# Generated by FakeRAM 2.0
VERSION 5.7 ;
BUSBITCHARS "[]" ;
PROPERTYDEFINITIONS
  MACRO width INTEGER ;
  MACRO depth INTEGER ;
  MACRO banks INTEGER ;
END PROPERTYDEFINITIONS
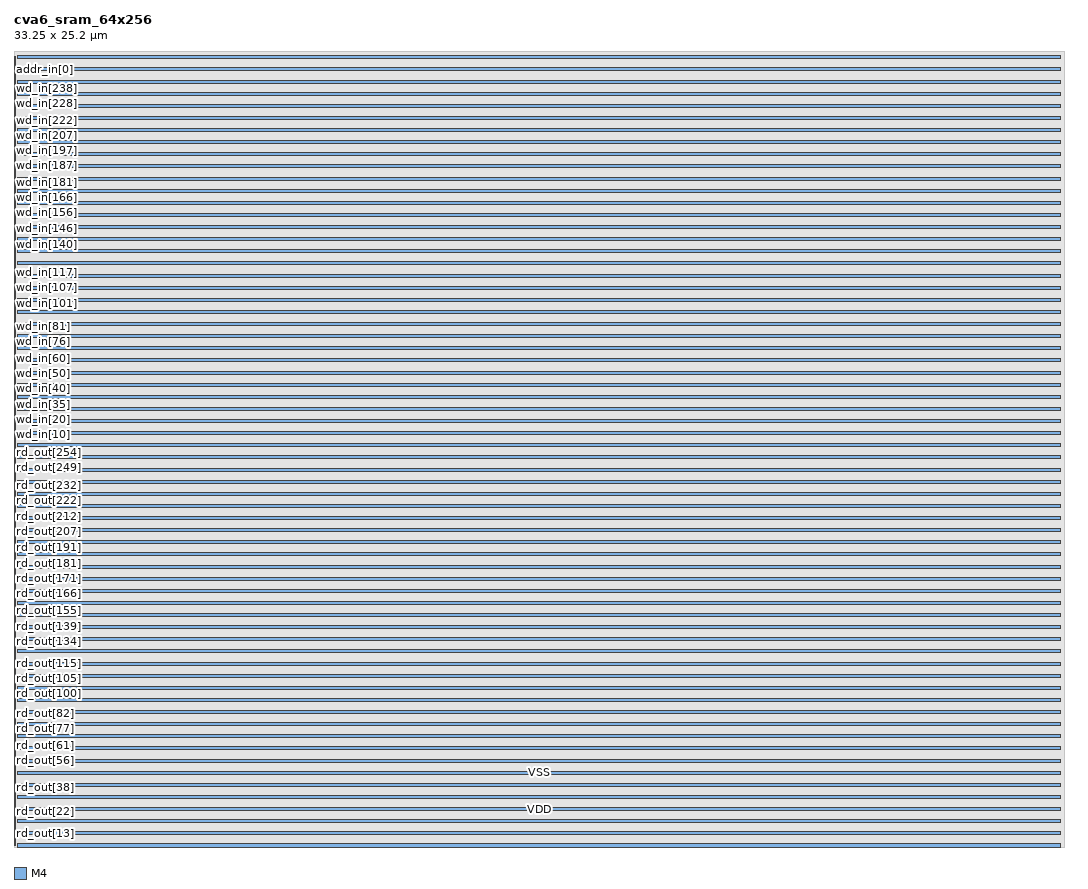
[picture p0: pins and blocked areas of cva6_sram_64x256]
MACRO cva6_sram_64x256
  PROPERTY width 256 ;
  PROPERTY depth 64 ;
  PROPERTY banks 1 ;
  FOREIGN cva6_sram_64x256 0 0 ;
  SYMMETRY X Y R90 ;
  SIZE 33.2500 BY 25.2000 ;
  CLASS BLOCK ;
  PIN rd_out[0]
    DIRECTION OUTPUT ;
    USE SIGNAL ;
    PORT
      LAYER M4 ;
      RECT 0.00000 0.04800 0.03600 0.07200 ;
    END
  END rd_out[0]
  PIN rd_out[1]
    DIRECTION OUTPUT ;
    USE SIGNAL ;
    PORT
      LAYER M4 ;
      RECT 0.00000 0.09600 0.03600 0.12000 ;
    END
  END rd_out[1]
  PIN rd_out[2]
    DIRECTION OUTPUT ;
    USE SIGNAL ;
    PORT
      LAYER M4 ;
      RECT 0.00000 0.14400 0.03600 0.16800 ;
    END
  END rd_out[2]
  PIN rd_out[3]
    DIRECTION OUTPUT ;
    USE SIGNAL ;
    PORT
      LAYER M4 ;
      RECT 0.00000 0.19200 0.03600 0.21600 ;
    END
  END rd_out[3]
  PIN rd_out[4]
    DIRECTION OUTPUT ;
    USE SIGNAL ;
    PORT
      LAYER M4 ;
      RECT 0.00000 0.24000 0.03600 0.26400 ;
    END
  END rd_out[4]
  PIN rd_out[5]
    DIRECTION OUTPUT ;
    USE SIGNAL ;
    PORT
      LAYER M4 ;
      RECT 0.00000 0.28800 0.03600 0.31200 ;
    END
  END rd_out[5]
  PIN rd_out[6]
    DIRECTION OUTPUT ;
    USE SIGNAL ;
    PORT
      LAYER M4 ;
      RECT 0.00000 0.33600 0.03600 0.36000 ;
    END
  END rd_out[6]
  PIN rd_out[7]
    DIRECTION OUTPUT ;
    USE SIGNAL ;
    PORT
      LAYER M4 ;
      RECT 0.00000 0.38400 0.03600 0.40800 ;
    END
  END rd_out[7]
  PIN rd_out[8]
    DIRECTION OUTPUT ;
    USE SIGNAL ;
    PORT
      LAYER M4 ;
      RECT 0.00000 0.43200 0.03600 0.45600 ;
    END
  END rd_out[8]
  PIN rd_out[9]
    DIRECTION OUTPUT ;
    USE SIGNAL ;
    PORT
      LAYER M4 ;
      RECT 0.00000 0.48000 0.03600 0.50400 ;
    END
  END rd_out[9]
  PIN rd_out[10]
    DIRECTION OUTPUT ;
    USE SIGNAL ;
    PORT
      LAYER M4 ;
      RECT 0.00000 0.52800 0.03600 0.55200 ;
    END
  END rd_out[10]
  PIN rd_out[11]
    DIRECTION OUTPUT ;
    USE SIGNAL ;
    PORT
      LAYER M4 ;
      RECT 0.00000 0.57600 0.03600 0.60000 ;
    END
  END rd_out[11]
  PIN rd_out[12]
    DIRECTION OUTPUT ;
    USE SIGNAL ;
    PORT
      LAYER M4 ;
      RECT 0.00000 0.62400 0.03600 0.64800 ;
    END
  END rd_out[12]
  PIN rd_out[13]
    DIRECTION OUTPUT ;
    USE SIGNAL ;
    PORT
      LAYER M4 ;
      RECT 0.00000 0.67200 0.03600 0.69600 ;
    END
  END rd_out[13]
  PIN rd_out[14]
    DIRECTION OUTPUT ;
    USE SIGNAL ;
    PORT
      LAYER M4 ;
      RECT 0.00000 0.72000 0.03600 0.74400 ;
    END
  END rd_out[14]
  PIN rd_out[15]
    DIRECTION OUTPUT ;
    USE SIGNAL ;
    PORT
      LAYER M4 ;
      RECT 0.00000 0.76800 0.03600 0.79200 ;
    END
  END rd_out[15]
  PIN rd_out[16]
    DIRECTION OUTPUT ;
    USE SIGNAL ;
    PORT
      LAYER M4 ;
      RECT 0.00000 0.81600 0.03600 0.84000 ;
    END
  END rd_out[16]
  PIN rd_out[17]
    DIRECTION OUTPUT ;
    USE SIGNAL ;
    PORT
      LAYER M4 ;
      RECT 0.00000 0.86400 0.03600 0.88800 ;
    END
  END rd_out[17]
  PIN rd_out[18]
    DIRECTION OUTPUT ;
    USE SIGNAL ;
    PORT
      LAYER M4 ;
      RECT 0.00000 0.91200 0.03600 0.93600 ;
    END
  END rd_out[18]
  PIN rd_out[19]
    DIRECTION OUTPUT ;
    USE SIGNAL ;
    PORT
      LAYER M4 ;
      RECT 0.00000 0.96000 0.03600 0.98400 ;
    END
  END rd_out[19]
  PIN rd_out[20]
    DIRECTION OUTPUT ;
    USE SIGNAL ;
    PORT
      LAYER M4 ;
      RECT 0.00000 1.00800 0.03600 1.03200 ;
    END
  END rd_out[20]
  PIN rd_out[21]
    DIRECTION OUTPUT ;
    USE SIGNAL ;
    PORT
      LAYER M4 ;
      RECT 0.00000 1.05600 0.03600 1.08000 ;
    END
  END rd_out[21]
  PIN rd_out[22]
    DIRECTION OUTPUT ;
    USE SIGNAL ;
    PORT
      LAYER M4 ;
      RECT 0.00000 1.10400 0.03600 1.12800 ;
    END
  END rd_out[22]
  PIN rd_out[23]
    DIRECTION OUTPUT ;
    USE SIGNAL ;
    PORT
      LAYER M4 ;
      RECT 0.00000 1.15200 0.03600 1.17600 ;
    END
  END rd_out[23]
  PIN rd_out[24]
    DIRECTION OUTPUT ;
    USE SIGNAL ;
    PORT
      LAYER M4 ;
      RECT 0.00000 1.20000 0.03600 1.22400 ;
    END
  END rd_out[24]
  PIN rd_out[25]
    DIRECTION OUTPUT ;
    USE SIGNAL ;
    PORT
      LAYER M4 ;
      RECT 0.00000 1.24800 0.03600 1.27200 ;
    END
  END rd_out[25]
  PIN rd_out[26]
    DIRECTION OUTPUT ;
    USE SIGNAL ;
    PORT
      LAYER M4 ;
      RECT 0.00000 1.29600 0.03600 1.32000 ;
    END
  END rd_out[26]
  PIN rd_out[27]
    DIRECTION OUTPUT ;
    USE SIGNAL ;
    PORT
      LAYER M4 ;
      RECT 0.00000 1.34400 0.03600 1.36800 ;
    END
  END rd_out[27]
  PIN rd_out[28]
    DIRECTION OUTPUT ;
    USE SIGNAL ;
    PORT
      LAYER M4 ;
      RECT 0.00000 1.39200 0.03600 1.41600 ;
    END
  END rd_out[28]
  PIN rd_out[29]
    DIRECTION OUTPUT ;
    USE SIGNAL ;
    PORT
      LAYER M4 ;
      RECT 0.00000 1.44000 0.03600 1.46400 ;
    END
  END rd_out[29]
  PIN rd_out[30]
    DIRECTION OUTPUT ;
    USE SIGNAL ;
    PORT
      LAYER M4 ;
      RECT 0.00000 1.48800 0.03600 1.51200 ;
    END
  END rd_out[30]
  PIN rd_out[31]
    DIRECTION OUTPUT ;
    USE SIGNAL ;
    PORT
      LAYER M4 ;
      RECT 0.00000 1.53600 0.03600 1.56000 ;
    END
  END rd_out[31]
  PIN rd_out[32]
    DIRECTION OUTPUT ;
    USE SIGNAL ;
    PORT
      LAYER M4 ;
      RECT 0.00000 1.58400 0.03600 1.60800 ;
    END
  END rd_out[32]
  PIN rd_out[33]
    DIRECTION OUTPUT ;
    USE SIGNAL ;
    PORT
      LAYER M4 ;
      RECT 0.00000 1.63200 0.03600 1.65600 ;
    END
  END rd_out[33]
  PIN rd_out[34]
    DIRECTION OUTPUT ;
    USE SIGNAL ;
    PORT
      LAYER M4 ;
      RECT 0.00000 1.68000 0.03600 1.70400 ;
    END
  END rd_out[34]
  PIN rd_out[35]
    DIRECTION OUTPUT ;
    USE SIGNAL ;
    PORT
      LAYER M4 ;
      RECT 0.00000 1.72800 0.03600 1.75200 ;
    END
  END rd_out[35]
  PIN rd_out[36]
    DIRECTION OUTPUT ;
    USE SIGNAL ;
    PORT
      LAYER M4 ;
      RECT 0.00000 1.77600 0.03600 1.80000 ;
    END
  END rd_out[36]
  PIN rd_out[37]
    DIRECTION OUTPUT ;
    USE SIGNAL ;
    PORT
      LAYER M4 ;
      RECT 0.00000 1.82400 0.03600 1.84800 ;
    END
  END rd_out[37]
  PIN rd_out[38]
    DIRECTION OUTPUT ;
    USE SIGNAL ;
    PORT
      LAYER M4 ;
      RECT 0.00000 1.87200 0.03600 1.89600 ;
    END
  END rd_out[38]
  PIN rd_out[39]
    DIRECTION OUTPUT ;
    USE SIGNAL ;
    PORT
      LAYER M4 ;
      RECT 0.00000 1.92000 0.03600 1.94400 ;
    END
  END rd_out[39]
  PIN rd_out[40]
    DIRECTION OUTPUT ;
    USE SIGNAL ;
    PORT
      LAYER M4 ;
      RECT 0.00000 1.96800 0.03600 1.99200 ;
    END
  END rd_out[40]
  PIN rd_out[41]
    DIRECTION OUTPUT ;
    USE SIGNAL ;
    PORT
      LAYER M4 ;
      RECT 0.00000 2.01600 0.03600 2.04000 ;
    END
  END rd_out[41]
  PIN rd_out[42]
    DIRECTION OUTPUT ;
    USE SIGNAL ;
    PORT
      LAYER M4 ;
      RECT 0.00000 2.06400 0.03600 2.08800 ;
    END
  END rd_out[42]
  PIN rd_out[43]
    DIRECTION OUTPUT ;
    USE SIGNAL ;
    PORT
      LAYER M4 ;
      RECT 0.00000 2.11200 0.03600 2.13600 ;
    END
  END rd_out[43]
  PIN rd_out[44]
    DIRECTION OUTPUT ;
    USE SIGNAL ;
    PORT
      LAYER M4 ;
      RECT 0.00000 2.16000 0.03600 2.18400 ;
    END
  END rd_out[44]
  PIN rd_out[45]
    DIRECTION OUTPUT ;
    USE SIGNAL ;
    PORT
      LAYER M4 ;
      RECT 0.00000 2.20800 0.03600 2.23200 ;
    END
  END rd_out[45]
  PIN rd_out[46]
    DIRECTION OUTPUT ;
    USE SIGNAL ;
    PORT
      LAYER M4 ;
      RECT 0.00000 2.25600 0.03600 2.28000 ;
    END
  END rd_out[46]
  PIN rd_out[47]
    DIRECTION OUTPUT ;
    USE SIGNAL ;
    PORT
      LAYER M4 ;
      RECT 0.00000 2.30400 0.03600 2.32800 ;
    END
  END rd_out[47]
  PIN rd_out[48]
    DIRECTION OUTPUT ;
    USE SIGNAL ;
    PORT
      LAYER M4 ;
      RECT 0.00000 2.35200 0.03600 2.37600 ;
    END
  END rd_out[48]
  PIN rd_out[49]
    DIRECTION OUTPUT ;
    USE SIGNAL ;
    PORT
      LAYER M4 ;
      RECT 0.00000 2.40000 0.03600 2.42400 ;
    END
  END rd_out[49]
  PIN rd_out[50]
    DIRECTION OUTPUT ;
    USE SIGNAL ;
    PORT
      LAYER M4 ;
      RECT 0.00000 2.44800 0.03600 2.47200 ;
    END
  END rd_out[50]
  PIN rd_out[51]
    DIRECTION OUTPUT ;
    USE SIGNAL ;
    PORT
      LAYER M4 ;
      RECT 0.00000 2.49600 0.03600 2.52000 ;
    END
  END rd_out[51]
  PIN rd_out[52]
    DIRECTION OUTPUT ;
    USE SIGNAL ;
    PORT
      LAYER M4 ;
      RECT 0.00000 2.54400 0.03600 2.56800 ;
    END
  END rd_out[52]
  PIN rd_out[53]
    DIRECTION OUTPUT ;
    USE SIGNAL ;
    PORT
      LAYER M4 ;
      RECT 0.00000 2.59200 0.03600 2.61600 ;
    END
  END rd_out[53]
  PIN rd_out[54]
    DIRECTION OUTPUT ;
    USE SIGNAL ;
    PORT
      LAYER M4 ;
      RECT 0.00000 2.64000 0.03600 2.66400 ;
    END
  END rd_out[54]
  PIN rd_out[55]
    DIRECTION OUTPUT ;
    USE SIGNAL ;
    PORT
      LAYER M4 ;
      RECT 0.00000 2.68800 0.03600 2.71200 ;
    END
  END rd_out[55]
  PIN rd_out[56]
    DIRECTION OUTPUT ;
    USE SIGNAL ;
    PORT
      LAYER M4 ;
      RECT 0.00000 2.73600 0.03600 2.76000 ;
    END
  END rd_out[56]
  PIN rd_out[57]
    DIRECTION OUTPUT ;
    USE SIGNAL ;
    PORT
      LAYER M4 ;
      RECT 0.00000 2.78400 0.03600 2.80800 ;
    END
  END rd_out[57]
  PIN rd_out[58]
    DIRECTION OUTPUT ;
    USE SIGNAL ;
    PORT
      LAYER M4 ;
      RECT 0.00000 2.83200 0.03600 2.85600 ;
    END
  END rd_out[58]
  PIN rd_out[59]
    DIRECTION OUTPUT ;
    USE SIGNAL ;
    PORT
      LAYER M4 ;
      RECT 0.00000 2.88000 0.03600 2.90400 ;
    END
  END rd_out[59]
  PIN rd_out[60]
    DIRECTION OUTPUT ;
    USE SIGNAL ;
    PORT
      LAYER M4 ;
      RECT 0.00000 2.92800 0.03600 2.95200 ;
    END
  END rd_out[60]
  PIN rd_out[61]
    DIRECTION OUTPUT ;
    USE SIGNAL ;
    PORT
      LAYER M4 ;
      RECT 0.00000 2.97600 0.03600 3.00000 ;
    END
  END rd_out[61]
  PIN rd_out[62]
    DIRECTION OUTPUT ;
    USE SIGNAL ;
    PORT
      LAYER M4 ;
      RECT 0.00000 3.02400 0.03600 3.04800 ;
    END
  END rd_out[62]
  PIN rd_out[63]
    DIRECTION OUTPUT ;
    USE SIGNAL ;
    PORT
      LAYER M4 ;
      RECT 0.00000 3.07200 0.03600 3.09600 ;
    END
  END rd_out[63]
  PIN rd_out[64]
    DIRECTION OUTPUT ;
    USE SIGNAL ;
    PORT
      LAYER M4 ;
      RECT 0.00000 3.12000 0.03600 3.14400 ;
    END
  END rd_out[64]
  PIN rd_out[65]
    DIRECTION OUTPUT ;
    USE SIGNAL ;
    PORT
      LAYER M4 ;
      RECT 0.00000 3.16800 0.03600 3.19200 ;
    END
  END rd_out[65]
  PIN rd_out[66]
    DIRECTION OUTPUT ;
    USE SIGNAL ;
    PORT
      LAYER M4 ;
      RECT 0.00000 3.21600 0.03600 3.24000 ;
    END
  END rd_out[66]
  PIN rd_out[67]
    DIRECTION OUTPUT ;
    USE SIGNAL ;
    PORT
      LAYER M4 ;
      RECT 0.00000 3.26400 0.03600 3.28800 ;
    END
  END rd_out[67]
  PIN rd_out[68]
    DIRECTION OUTPUT ;
    USE SIGNAL ;
    PORT
      LAYER M4 ;
      RECT 0.00000 3.31200 0.03600 3.33600 ;
    END
  END rd_out[68]
  PIN rd_out[69]
    DIRECTION OUTPUT ;
    USE SIGNAL ;
    PORT
      LAYER M4 ;
      RECT 0.00000 3.36000 0.03600 3.38400 ;
    END
  END rd_out[69]
  PIN rd_out[70]
    DIRECTION OUTPUT ;
    USE SIGNAL ;
    PORT
      LAYER M4 ;
      RECT 0.00000 3.40800 0.03600 3.43200 ;
    END
  END rd_out[70]
  PIN rd_out[71]
    DIRECTION OUTPUT ;
    USE SIGNAL ;
    PORT
      LAYER M4 ;
      RECT 0.00000 3.45600 0.03600 3.48000 ;
    END
  END rd_out[71]
  PIN rd_out[72]
    DIRECTION OUTPUT ;
    USE SIGNAL ;
    PORT
      LAYER M4 ;
      RECT 0.00000 3.50400 0.03600 3.52800 ;
    END
  END rd_out[72]
  PIN rd_out[73]
    DIRECTION OUTPUT ;
    USE SIGNAL ;
    PORT
      LAYER M4 ;
      RECT 0.00000 3.55200 0.03600 3.57600 ;
    END
  END rd_out[73]
  PIN rd_out[74]
    DIRECTION OUTPUT ;
    USE SIGNAL ;
    PORT
      LAYER M4 ;
      RECT 0.00000 3.60000 0.03600 3.62400 ;
    END
  END rd_out[74]
  PIN rd_out[75]
    DIRECTION OUTPUT ;
    USE SIGNAL ;
    PORT
      LAYER M4 ;
      RECT 0.00000 3.64800 0.03600 3.67200 ;
    END
  END rd_out[75]
  PIN rd_out[76]
    DIRECTION OUTPUT ;
    USE SIGNAL ;
    PORT
      LAYER M4 ;
      RECT 0.00000 3.69600 0.03600 3.72000 ;
    END
  END rd_out[76]
  PIN rd_out[77]
    DIRECTION OUTPUT ;
    USE SIGNAL ;
    PORT
      LAYER M4 ;
      RECT 0.00000 3.74400 0.03600 3.76800 ;
    END
  END rd_out[77]
  PIN rd_out[78]
    DIRECTION OUTPUT ;
    USE SIGNAL ;
    PORT
      LAYER M4 ;
      RECT 0.00000 3.79200 0.03600 3.81600 ;
    END
  END rd_out[78]
  PIN rd_out[79]
    DIRECTION OUTPUT ;
    USE SIGNAL ;
    PORT
      LAYER M4 ;
      RECT 0.00000 3.84000 0.03600 3.86400 ;
    END
  END rd_out[79]
  PIN rd_out[80]
    DIRECTION OUTPUT ;
    USE SIGNAL ;
    PORT
      LAYER M4 ;
      RECT 0.00000 3.88800 0.03600 3.91200 ;
    END
  END rd_out[80]
  PIN rd_out[81]
    DIRECTION OUTPUT ;
    USE SIGNAL ;
    PORT
      LAYER M4 ;
      RECT 0.00000 3.93600 0.03600 3.96000 ;
    END
  END rd_out[81]
  PIN rd_out[82]
    DIRECTION OUTPUT ;
    USE SIGNAL ;
    PORT
      LAYER M4 ;
      RECT 0.00000 3.98400 0.03600 4.00800 ;
    END
  END rd_out[82]
  PIN rd_out[83]
    DIRECTION OUTPUT ;
    USE SIGNAL ;
    PORT
      LAYER M4 ;
      RECT 0.00000 4.03200 0.03600 4.05600 ;
    END
  END rd_out[83]
  PIN rd_out[84]
    DIRECTION OUTPUT ;
    USE SIGNAL ;
    PORT
      LAYER M4 ;
      RECT 0.00000 4.08000 0.03600 4.10400 ;
    END
  END rd_out[84]
  PIN rd_out[85]
    DIRECTION OUTPUT ;
    USE SIGNAL ;
    PORT
      LAYER M4 ;
      RECT 0.00000 4.12800 0.03600 4.15200 ;
    END
  END rd_out[85]
  PIN rd_out[86]
    DIRECTION OUTPUT ;
    USE SIGNAL ;
    PORT
      LAYER M4 ;
      RECT 0.00000 4.17600 0.03600 4.20000 ;
    END
  END rd_out[86]
  PIN rd_out[87]
    DIRECTION OUTPUT ;
    USE SIGNAL ;
    PORT
      LAYER M4 ;
      RECT 0.00000 4.22400 0.03600 4.24800 ;
    END
  END rd_out[87]
  PIN rd_out[88]
    DIRECTION OUTPUT ;
    USE SIGNAL ;
    PORT
      LAYER M4 ;
      RECT 0.00000 4.27200 0.03600 4.29600 ;
    END
  END rd_out[88]
  PIN rd_out[89]
    DIRECTION OUTPUT ;
    USE SIGNAL ;
    PORT
      LAYER M4 ;
      RECT 0.00000 4.32000 0.03600 4.34400 ;
    END
  END rd_out[89]
  PIN rd_out[90]
    DIRECTION OUTPUT ;
    USE SIGNAL ;
    PORT
      LAYER M4 ;
      RECT 0.00000 4.36800 0.03600 4.39200 ;
    END
  END rd_out[90]
  PIN rd_out[91]
    DIRECTION OUTPUT ;
    USE SIGNAL ;
    PORT
      LAYER M4 ;
      RECT 0.00000 4.41600 0.03600 4.44000 ;
    END
  END rd_out[91]
  PIN rd_out[92]
    DIRECTION OUTPUT ;
    USE SIGNAL ;
    PORT
      LAYER M4 ;
      RECT 0.00000 4.46400 0.03600 4.48800 ;
    END
  END rd_out[92]
  PIN rd_out[93]
    DIRECTION OUTPUT ;
    USE SIGNAL ;
    PORT
      LAYER M4 ;
      RECT 0.00000 4.51200 0.03600 4.53600 ;
    END
  END rd_out[93]
  PIN rd_out[94]
    DIRECTION OUTPUT ;
    USE SIGNAL ;
    PORT
      LAYER M4 ;
      RECT 0.00000 4.56000 0.03600 4.58400 ;
    END
  END rd_out[94]
  PIN rd_out[95]
    DIRECTION OUTPUT ;
    USE SIGNAL ;
    PORT
      LAYER M4 ;
      RECT 0.00000 4.60800 0.03600 4.63200 ;
    END
  END rd_out[95]
  PIN rd_out[96]
    DIRECTION OUTPUT ;
    USE SIGNAL ;
    PORT
      LAYER M4 ;
      RECT 0.00000 4.65600 0.03600 4.68000 ;
    END
  END rd_out[96]
  PIN rd_out[97]
    DIRECTION OUTPUT ;
    USE SIGNAL ;
    PORT
      LAYER M4 ;
      RECT 0.00000 4.70400 0.03600 4.72800 ;
    END
  END rd_out[97]
  PIN rd_out[98]
    DIRECTION OUTPUT ;
    USE SIGNAL ;
    PORT
      LAYER M4 ;
      RECT 0.00000 4.75200 0.03600 4.77600 ;
    END
  END rd_out[98]
  PIN rd_out[99]
    DIRECTION OUTPUT ;
    USE SIGNAL ;
    PORT
      LAYER M4 ;
      RECT 0.00000 4.80000 0.03600 4.82400 ;
    END
  END rd_out[99]
  PIN rd_out[100]
    DIRECTION OUTPUT ;
    USE SIGNAL ;
    PORT
      LAYER M4 ;
      RECT 0.00000 4.84800 0.03600 4.87200 ;
    END
  END rd_out[100]
  PIN rd_out[101]
    DIRECTION OUTPUT ;
    USE SIGNAL ;
    PORT
      LAYER M4 ;
      RECT 0.00000 4.89600 0.03600 4.92000 ;
    END
  END rd_out[101]
  PIN rd_out[102]
    DIRECTION OUTPUT ;
    USE SIGNAL ;
    PORT
      LAYER M4 ;
      RECT 0.00000 4.94400 0.03600 4.96800 ;
    END
  END rd_out[102]
  PIN rd_out[103]
    DIRECTION OUTPUT ;
    USE SIGNAL ;
    PORT
      LAYER M4 ;
      RECT 0.00000 4.99200 0.03600 5.01600 ;
    END
  END rd_out[103]
  PIN rd_out[104]
    DIRECTION OUTPUT ;
    USE SIGNAL ;
    PORT
      LAYER M4 ;
      RECT 0.00000 5.04000 0.03600 5.06400 ;
    END
  END rd_out[104]
  PIN rd_out[105]
    DIRECTION OUTPUT ;
    USE SIGNAL ;
    PORT
      LAYER M4 ;
      RECT 0.00000 5.08800 0.03600 5.11200 ;
    END
  END rd_out[105]
  PIN rd_out[106]
    DIRECTION OUTPUT ;
    USE SIGNAL ;
    PORT
      LAYER M4 ;
      RECT 0.00000 5.13600 0.03600 5.16000 ;
    END
  END rd_out[106]
  PIN rd_out[107]
    DIRECTION OUTPUT ;
    USE SIGNAL ;
    PORT
      LAYER M4 ;
      RECT 0.00000 5.18400 0.03600 5.20800 ;
    END
  END rd_out[107]
  PIN rd_out[108]
    DIRECTION OUTPUT ;
    USE SIGNAL ;
    PORT
      LAYER M4 ;
      RECT 0.00000 5.23200 0.03600 5.25600 ;
    END
  END rd_out[108]
  PIN rd_out[109]
    DIRECTION OUTPUT ;
    USE SIGNAL ;
    PORT
      LAYER M4 ;
      RECT 0.00000 5.28000 0.03600 5.30400 ;
    END
  END rd_out[109]
  PIN rd_out[110]
    DIRECTION OUTPUT ;
    USE SIGNAL ;
    PORT
      LAYER M4 ;
      RECT 0.00000 5.32800 0.03600 5.35200 ;
    END
  END rd_out[110]
  PIN rd_out[111]
    DIRECTION OUTPUT ;
    USE SIGNAL ;
    PORT
      LAYER M4 ;
      RECT 0.00000 5.37600 0.03600 5.40000 ;
    END
  END rd_out[111]
  PIN rd_out[112]
    DIRECTION OUTPUT ;
    USE SIGNAL ;
    PORT
      LAYER M4 ;
      RECT 0.00000 5.42400 0.03600 5.44800 ;
    END
  END rd_out[112]
  PIN rd_out[113]
    DIRECTION OUTPUT ;
    USE SIGNAL ;
    PORT
      LAYER M4 ;
      RECT 0.00000 5.47200 0.03600 5.49600 ;
    END
  END rd_out[113]
  PIN rd_out[114]
    DIRECTION OUTPUT ;
    USE SIGNAL ;
    PORT
      LAYER M4 ;
      RECT 0.00000 5.52000 0.03600 5.54400 ;
    END
  END rd_out[114]
  PIN rd_out[115]
    DIRECTION OUTPUT ;
    USE SIGNAL ;
    PORT
      LAYER M4 ;
      RECT 0.00000 5.56800 0.03600 5.59200 ;
    END
  END rd_out[115]
  PIN rd_out[116]
    DIRECTION OUTPUT ;
    USE SIGNAL ;
    PORT
      LAYER M4 ;
      RECT 0.00000 5.61600 0.03600 5.64000 ;
    END
  END rd_out[116]
  PIN rd_out[117]
    DIRECTION OUTPUT ;
    USE SIGNAL ;
    PORT
      LAYER M4 ;
      RECT 0.00000 5.66400 0.03600 5.68800 ;
    END
  END rd_out[117]
  PIN rd_out[118]
    DIRECTION OUTPUT ;
    USE SIGNAL ;
    PORT
      LAYER M4 ;
      RECT 0.00000 5.71200 0.03600 5.73600 ;
    END
  END rd_out[118]
  PIN rd_out[119]
    DIRECTION OUTPUT ;
    USE SIGNAL ;
    PORT
      LAYER M4 ;
      RECT 0.00000 5.76000 0.03600 5.78400 ;
    END
  END rd_out[119]
  PIN rd_out[120]
    DIRECTION OUTPUT ;
    USE SIGNAL ;
    PORT
      LAYER M4 ;
      RECT 0.00000 5.80800 0.03600 5.83200 ;
    END
  END rd_out[120]
  PIN rd_out[121]
    DIRECTION OUTPUT ;
    USE SIGNAL ;
    PORT
      LAYER M4 ;
      RECT 0.00000 5.85600 0.03600 5.88000 ;
    END
  END rd_out[121]
  PIN rd_out[122]
    DIRECTION OUTPUT ;
    USE SIGNAL ;
    PORT
      LAYER M4 ;
      RECT 0.00000 5.90400 0.03600 5.92800 ;
    END
  END rd_out[122]
  PIN rd_out[123]
    DIRECTION OUTPUT ;
    USE SIGNAL ;
    PORT
      LAYER M4 ;
      RECT 0.00000 5.95200 0.03600 5.97600 ;
    END
  END rd_out[123]
  PIN rd_out[124]
    DIRECTION OUTPUT ;
    USE SIGNAL ;
    PORT
      LAYER M4 ;
      RECT 0.00000 6.00000 0.03600 6.02400 ;
    END
  END rd_out[124]
  PIN rd_out[125]
    DIRECTION OUTPUT ;
    USE SIGNAL ;
    PORT
      LAYER M4 ;
      RECT 0.00000 6.04800 0.03600 6.07200 ;
    END
  END rd_out[125]
  PIN rd_out[126]
    DIRECTION OUTPUT ;
    USE SIGNAL ;
    PORT
      LAYER M4 ;
      RECT 0.00000 6.09600 0.03600 6.12000 ;
    END
  END rd_out[126]
  PIN rd_out[127]
    DIRECTION OUTPUT ;
    USE SIGNAL ;
    PORT
      LAYER M4 ;
      RECT 0.00000 6.14400 0.03600 6.16800 ;
    END
  END rd_out[127]
  PIN rd_out[128]
    DIRECTION OUTPUT ;
    USE SIGNAL ;
    PORT
      LAYER M4 ;
      RECT 0.00000 6.19200 0.03600 6.21600 ;
    END
  END rd_out[128]
  PIN rd_out[129]
    DIRECTION OUTPUT ;
    USE SIGNAL ;
    PORT
      LAYER M4 ;
      RECT 0.00000 6.24000 0.03600 6.26400 ;
    END
  END rd_out[129]
  PIN rd_out[130]
    DIRECTION OUTPUT ;
    USE SIGNAL ;
    PORT
      LAYER M4 ;
      RECT 0.00000 6.28800 0.03600 6.31200 ;
    END
  END rd_out[130]
  PIN rd_out[131]
    DIRECTION OUTPUT ;
    USE SIGNAL ;
    PORT
      LAYER M4 ;
      RECT 0.00000 6.33600 0.03600 6.36000 ;
    END
  END rd_out[131]
  PIN rd_out[132]
    DIRECTION OUTPUT ;
    USE SIGNAL ;
    PORT
      LAYER M4 ;
      RECT 0.00000 6.38400 0.03600 6.40800 ;
    END
  END rd_out[132]
  PIN rd_out[133]
    DIRECTION OUTPUT ;
    USE SIGNAL ;
    PORT
      LAYER M4 ;
      RECT 0.00000 6.43200 0.03600 6.45600 ;
    END
  END rd_out[133]
  PIN rd_out[134]
    DIRECTION OUTPUT ;
    USE SIGNAL ;
    PORT
      LAYER M4 ;
      RECT 0.00000 6.48000 0.03600 6.50400 ;
    END
  END rd_out[134]
  PIN rd_out[135]
    DIRECTION OUTPUT ;
    USE SIGNAL ;
    PORT
      LAYER M4 ;
      RECT 0.00000 6.52800 0.03600 6.55200 ;
    END
  END rd_out[135]
  PIN rd_out[136]
    DIRECTION OUTPUT ;
    USE SIGNAL ;
    PORT
      LAYER M4 ;
      RECT 0.00000 6.57600 0.03600 6.60000 ;
    END
  END rd_out[136]
  PIN rd_out[137]
    DIRECTION OUTPUT ;
    USE SIGNAL ;
    PORT
      LAYER M4 ;
      RECT 0.00000 6.62400 0.03600 6.64800 ;
    END
  END rd_out[137]
  PIN rd_out[138]
    DIRECTION OUTPUT ;
    USE SIGNAL ;
    PORT
      LAYER M4 ;
      RECT 0.00000 6.67200 0.03600 6.69600 ;
    END
  END rd_out[138]
  PIN rd_out[139]
    DIRECTION OUTPUT ;
    USE SIGNAL ;
    PORT
      LAYER M4 ;
      RECT 0.00000 6.72000 0.03600 6.74400 ;
    END
  END rd_out[139]
  PIN rd_out[140]
    DIRECTION OUTPUT ;
    USE SIGNAL ;
    PORT
      LAYER M4 ;
      RECT 0.00000 6.76800 0.03600 6.79200 ;
    END
  END rd_out[140]
  PIN rd_out[141]
    DIRECTION OUTPUT ;
    USE SIGNAL ;
    PORT
      LAYER M4 ;
      RECT 0.00000 6.81600 0.03600 6.84000 ;
    END
  END rd_out[141]
  PIN rd_out[142]
    DIRECTION OUTPUT ;
    USE SIGNAL ;
    PORT
      LAYER M4 ;
      RECT 0.00000 6.86400 0.03600 6.88800 ;
    END
  END rd_out[142]
  PIN rd_out[143]
    DIRECTION OUTPUT ;
    USE SIGNAL ;
    PORT
      LAYER M4 ;
      RECT 0.00000 6.91200 0.03600 6.93600 ;
    END
  END rd_out[143]
  PIN rd_out[144]
    DIRECTION OUTPUT ;
    USE SIGNAL ;
    PORT
      LAYER M4 ;
      RECT 0.00000 6.96000 0.03600 6.98400 ;
    END
  END rd_out[144]
  PIN rd_out[145]
    DIRECTION OUTPUT ;
    USE SIGNAL ;
    PORT
      LAYER M4 ;
      RECT 0.00000 7.00800 0.03600 7.03200 ;
    END
  END rd_out[145]
  PIN rd_out[146]
    DIRECTION OUTPUT ;
    USE SIGNAL ;
    PORT
      LAYER M4 ;
      RECT 0.00000 7.05600 0.03600 7.08000 ;
    END
  END rd_out[146]
  PIN rd_out[147]
    DIRECTION OUTPUT ;
    USE SIGNAL ;
    PORT
      LAYER M4 ;
      RECT 0.00000 7.10400 0.03600 7.12800 ;
    END
  END rd_out[147]
  PIN rd_out[148]
    DIRECTION OUTPUT ;
    USE SIGNAL ;
    PORT
      LAYER M4 ;
      RECT 0.00000 7.15200 0.03600 7.17600 ;
    END
  END rd_out[148]
  PIN rd_out[149]
    DIRECTION OUTPUT ;
    USE SIGNAL ;
    PORT
      LAYER M4 ;
      RECT 0.00000 7.20000 0.03600 7.22400 ;
    END
  END rd_out[149]
  PIN rd_out[150]
    DIRECTION OUTPUT ;
    USE SIGNAL ;
    PORT
      LAYER M4 ;
      RECT 0.00000 7.24800 0.03600 7.27200 ;
    END
  END rd_out[150]
  PIN rd_out[151]
    DIRECTION OUTPUT ;
    USE SIGNAL ;
    PORT
      LAYER M4 ;
      RECT 0.00000 7.29600 0.03600 7.32000 ;
    END
  END rd_out[151]
  PIN rd_out[152]
    DIRECTION OUTPUT ;
    USE SIGNAL ;
    PORT
      LAYER M4 ;
      RECT 0.00000 7.34400 0.03600 7.36800 ;
    END
  END rd_out[152]
  PIN rd_out[153]
    DIRECTION OUTPUT ;
    USE SIGNAL ;
    PORT
      LAYER M4 ;
      RECT 0.00000 7.39200 0.03600 7.41600 ;
    END
  END rd_out[153]
  PIN rd_out[154]
    DIRECTION OUTPUT ;
    USE SIGNAL ;
    PORT
      LAYER M4 ;
      RECT 0.00000 7.44000 0.03600 7.46400 ;
    END
  END rd_out[154]
  PIN rd_out[155]
    DIRECTION OUTPUT ;
    USE SIGNAL ;
    PORT
      LAYER M4 ;
      RECT 0.00000 7.48800 0.03600 7.51200 ;
    END
  END rd_out[155]
  PIN rd_out[156]
    DIRECTION OUTPUT ;
    USE SIGNAL ;
    PORT
      LAYER M4 ;
      RECT 0.00000 7.53600 0.03600 7.56000 ;
    END
  END rd_out[156]
  PIN rd_out[157]
    DIRECTION OUTPUT ;
    USE SIGNAL ;
    PORT
      LAYER M4 ;
      RECT 0.00000 7.58400 0.03600 7.60800 ;
    END
  END rd_out[157]
  PIN rd_out[158]
    DIRECTION OUTPUT ;
    USE SIGNAL ;
    PORT
      LAYER M4 ;
      RECT 0.00000 7.63200 0.03600 7.65600 ;
    END
  END rd_out[158]
  PIN rd_out[159]
    DIRECTION OUTPUT ;
    USE SIGNAL ;
    PORT
      LAYER M4 ;
      RECT 0.00000 7.68000 0.03600 7.70400 ;
    END
  END rd_out[159]
  PIN rd_out[160]
    DIRECTION OUTPUT ;
    USE SIGNAL ;
    PORT
      LAYER M4 ;
      RECT 0.00000 7.72800 0.03600 7.75200 ;
    END
  END rd_out[160]
  PIN rd_out[161]
    DIRECTION OUTPUT ;
    USE SIGNAL ;
    PORT
      LAYER M4 ;
      RECT 0.00000 7.77600 0.03600 7.80000 ;
    END
  END rd_out[161]
  PIN rd_out[162]
    DIRECTION OUTPUT ;
    USE SIGNAL ;
    PORT
      LAYER M4 ;
      RECT 0.00000 7.82400 0.03600 7.84800 ;
    END
  END rd_out[162]
  PIN rd_out[163]
    DIRECTION OUTPUT ;
    USE SIGNAL ;
    PORT
      LAYER M4 ;
      RECT 0.00000 7.87200 0.03600 7.89600 ;
    END
  END rd_out[163]
  PIN rd_out[164]
    DIRECTION OUTPUT ;
    USE SIGNAL ;
    PORT
      LAYER M4 ;
      RECT 0.00000 7.92000 0.03600 7.94400 ;
    END
  END rd_out[164]
  PIN rd_out[165]
    DIRECTION OUTPUT ;
    USE SIGNAL ;
    PORT
      LAYER M4 ;
      RECT 0.00000 7.96800 0.03600 7.99200 ;
    END
  END rd_out[165]
  PIN rd_out[166]
    DIRECTION OUTPUT ;
    USE SIGNAL ;
    PORT
      LAYER M4 ;
      RECT 0.00000 8.01600 0.03600 8.04000 ;
    END
  END rd_out[166]
  PIN rd_out[167]
    DIRECTION OUTPUT ;
    USE SIGNAL ;
    PORT
      LAYER M4 ;
      RECT 0.00000 8.06400 0.03600 8.08800 ;
    END
  END rd_out[167]
  PIN rd_out[168]
    DIRECTION OUTPUT ;
    USE SIGNAL ;
    PORT
      LAYER M4 ;
      RECT 0.00000 8.11200 0.03600 8.13600 ;
    END
  END rd_out[168]
  PIN rd_out[169]
    DIRECTION OUTPUT ;
    USE SIGNAL ;
    PORT
      LAYER M4 ;
      RECT 0.00000 8.16000 0.03600 8.18400 ;
    END
  END rd_out[169]
  PIN rd_out[170]
    DIRECTION OUTPUT ;
    USE SIGNAL ;
    PORT
      LAYER M4 ;
      RECT 0.00000 8.20800 0.03600 8.23200 ;
    END
  END rd_out[170]
  PIN rd_out[171]
    DIRECTION OUTPUT ;
    USE SIGNAL ;
    PORT
      LAYER M4 ;
      RECT 0.00000 8.25600 0.03600 8.28000 ;
    END
  END rd_out[171]
  PIN rd_out[172]
    DIRECTION OUTPUT ;
    USE SIGNAL ;
    PORT
      LAYER M4 ;
      RECT 0.00000 8.30400 0.03600 8.32800 ;
    END
  END rd_out[172]
  PIN rd_out[173]
    DIRECTION OUTPUT ;
    USE SIGNAL ;
    PORT
      LAYER M4 ;
      RECT 0.00000 8.35200 0.03600 8.37600 ;
    END
  END rd_out[173]
  PIN rd_out[174]
    DIRECTION OUTPUT ;
    USE SIGNAL ;
    PORT
      LAYER M4 ;
      RECT 0.00000 8.40000 0.03600 8.42400 ;
    END
  END rd_out[174]
  PIN rd_out[175]
    DIRECTION OUTPUT ;
    USE SIGNAL ;
    PORT
      LAYER M4 ;
      RECT 0.00000 8.44800 0.03600 8.47200 ;
    END
  END rd_out[175]
  PIN rd_out[176]
    DIRECTION OUTPUT ;
    USE SIGNAL ;
    PORT
      LAYER M4 ;
      RECT 0.00000 8.49600 0.03600 8.52000 ;
    END
  END rd_out[176]
  PIN rd_out[177]
    DIRECTION OUTPUT ;
    USE SIGNAL ;
    PORT
      LAYER M4 ;
      RECT 0.00000 8.54400 0.03600 8.56800 ;
    END
  END rd_out[177]
  PIN rd_out[178]
    DIRECTION OUTPUT ;
    USE SIGNAL ;
    PORT
      LAYER M4 ;
      RECT 0.00000 8.59200 0.03600 8.61600 ;
    END
  END rd_out[178]
  PIN rd_out[179]
    DIRECTION OUTPUT ;
    USE SIGNAL ;
    PORT
      LAYER M4 ;
      RECT 0.00000 8.64000 0.03600 8.66400 ;
    END
  END rd_out[179]
  PIN rd_out[180]
    DIRECTION OUTPUT ;
    USE SIGNAL ;
    PORT
      LAYER M4 ;
      RECT 0.00000 8.68800 0.03600 8.71200 ;
    END
  END rd_out[180]
  PIN rd_out[181]
    DIRECTION OUTPUT ;
    USE SIGNAL ;
    PORT
      LAYER M4 ;
      RECT 0.00000 8.73600 0.03600 8.76000 ;
    END
  END rd_out[181]
  PIN rd_out[182]
    DIRECTION OUTPUT ;
    USE SIGNAL ;
    PORT
      LAYER M4 ;
      RECT 0.00000 8.78400 0.03600 8.80800 ;
    END
  END rd_out[182]
  PIN rd_out[183]
    DIRECTION OUTPUT ;
    USE SIGNAL ;
    PORT
      LAYER M4 ;
      RECT 0.00000 8.83200 0.03600 8.85600 ;
    END
  END rd_out[183]
  PIN rd_out[184]
    DIRECTION OUTPUT ;
    USE SIGNAL ;
    PORT
      LAYER M4 ;
      RECT 0.00000 8.88000 0.03600 8.90400 ;
    END
  END rd_out[184]
  PIN rd_out[185]
    DIRECTION OUTPUT ;
    USE SIGNAL ;
    PORT
      LAYER M4 ;
      RECT 0.00000 8.92800 0.03600 8.95200 ;
    END
  END rd_out[185]
  PIN rd_out[186]
    DIRECTION OUTPUT ;
    USE SIGNAL ;
    PORT
      LAYER M4 ;
      RECT 0.00000 8.97600 0.03600 9.00000 ;
    END
  END rd_out[186]
  PIN rd_out[187]
    DIRECTION OUTPUT ;
    USE SIGNAL ;
    PORT
      LAYER M4 ;
      RECT 0.00000 9.02400 0.03600 9.04800 ;
    END
  END rd_out[187]
  PIN rd_out[188]
    DIRECTION OUTPUT ;
    USE SIGNAL ;
    PORT
      LAYER M4 ;
      RECT 0.00000 9.07200 0.03600 9.09600 ;
    END
  END rd_out[188]
  PIN rd_out[189]
    DIRECTION OUTPUT ;
    USE SIGNAL ;
    PORT
      LAYER M4 ;
      RECT 0.00000 9.12000 0.03600 9.14400 ;
    END
  END rd_out[189]
  PIN rd_out[190]
    DIRECTION OUTPUT ;
    USE SIGNAL ;
    PORT
      LAYER M4 ;
      RECT 0.00000 9.16800 0.03600 9.19200 ;
    END
  END rd_out[190]
  PIN rd_out[191]
    DIRECTION OUTPUT ;
    USE SIGNAL ;
    PORT
      LAYER M4 ;
      RECT 0.00000 9.21600 0.03600 9.24000 ;
    END
  END rd_out[191]
  PIN rd_out[192]
    DIRECTION OUTPUT ;
    USE SIGNAL ;
    PORT
      LAYER M4 ;
      RECT 0.00000 9.26400 0.03600 9.28800 ;
    END
  END rd_out[192]
  PIN rd_out[193]
    DIRECTION OUTPUT ;
    USE SIGNAL ;
    PORT
      LAYER M4 ;
      RECT 0.00000 9.31200 0.03600 9.33600 ;
    END
  END rd_out[193]
  PIN rd_out[194]
    DIRECTION OUTPUT ;
    USE SIGNAL ;
    PORT
      LAYER M4 ;
      RECT 0.00000 9.36000 0.03600 9.38400 ;
    END
  END rd_out[194]
  PIN rd_out[195]
    DIRECTION OUTPUT ;
    USE SIGNAL ;
    PORT
      LAYER M4 ;
      RECT 0.00000 9.40800 0.03600 9.43200 ;
    END
  END rd_out[195]
  PIN rd_out[196]
    DIRECTION OUTPUT ;
    USE SIGNAL ;
    PORT
      LAYER M4 ;
      RECT 0.00000 9.45600 0.03600 9.48000 ;
    END
  END rd_out[196]
  PIN rd_out[197]
    DIRECTION OUTPUT ;
    USE SIGNAL ;
    PORT
      LAYER M4 ;
      RECT 0.00000 9.50400 0.03600 9.52800 ;
    END
  END rd_out[197]
  PIN rd_out[198]
    DIRECTION OUTPUT ;
    USE SIGNAL ;
    PORT
      LAYER M4 ;
      RECT 0.00000 9.55200 0.03600 9.57600 ;
    END
  END rd_out[198]
  PIN rd_out[199]
    DIRECTION OUTPUT ;
    USE SIGNAL ;
    PORT
      LAYER M4 ;
      RECT 0.00000 9.60000 0.03600 9.62400 ;
    END
  END rd_out[199]
  PIN rd_out[200]
    DIRECTION OUTPUT ;
    USE SIGNAL ;
    PORT
      LAYER M4 ;
      RECT 0.00000 9.64800 0.03600 9.67200 ;
    END
  END rd_out[200]
  PIN rd_out[201]
    DIRECTION OUTPUT ;
    USE SIGNAL ;
    PORT
      LAYER M4 ;
      RECT 0.00000 9.69600 0.03600 9.72000 ;
    END
  END rd_out[201]
  PIN rd_out[202]
    DIRECTION OUTPUT ;
    USE SIGNAL ;
    PORT
      LAYER M4 ;
      RECT 0.00000 9.74400 0.03600 9.76800 ;
    END
  END rd_out[202]
  PIN rd_out[203]
    DIRECTION OUTPUT ;
    USE SIGNAL ;
    PORT
      LAYER M4 ;
      RECT 0.00000 9.79200 0.03600 9.81600 ;
    END
  END rd_out[203]
  PIN rd_out[204]
    DIRECTION OUTPUT ;
    USE SIGNAL ;
    PORT
      LAYER M4 ;
      RECT 0.00000 9.84000 0.03600 9.86400 ;
    END
  END rd_out[204]
  PIN rd_out[205]
    DIRECTION OUTPUT ;
    USE SIGNAL ;
    PORT
      LAYER M4 ;
      RECT 0.00000 9.88800 0.03600 9.91200 ;
    END
  END rd_out[205]
  PIN rd_out[206]
    DIRECTION OUTPUT ;
    USE SIGNAL ;
    PORT
      LAYER M4 ;
      RECT 0.00000 9.93600 0.03600 9.96000 ;
    END
  END rd_out[206]
  PIN rd_out[207]
    DIRECTION OUTPUT ;
    USE SIGNAL ;
    PORT
      LAYER M4 ;
      RECT 0.00000 9.98400 0.03600 10.00800 ;
    END
  END rd_out[207]
  PIN rd_out[208]
    DIRECTION OUTPUT ;
    USE SIGNAL ;
    PORT
      LAYER M4 ;
      RECT 0.00000 10.03200 0.03600 10.05600 ;
    END
  END rd_out[208]
  PIN rd_out[209]
    DIRECTION OUTPUT ;
    USE SIGNAL ;
    PORT
      LAYER M4 ;
      RECT 0.00000 10.08000 0.03600 10.10400 ;
    END
  END rd_out[209]
  PIN rd_out[210]
    DIRECTION OUTPUT ;
    USE SIGNAL ;
    PORT
      LAYER M4 ;
      RECT 0.00000 10.12800 0.03600 10.15200 ;
    END
  END rd_out[210]
  PIN rd_out[211]
    DIRECTION OUTPUT ;
    USE SIGNAL ;
    PORT
      LAYER M4 ;
      RECT 0.00000 10.17600 0.03600 10.20000 ;
    END
  END rd_out[211]
  PIN rd_out[212]
    DIRECTION OUTPUT ;
    USE SIGNAL ;
    PORT
      LAYER M4 ;
      RECT 0.00000 10.22400 0.03600 10.24800 ;
    END
  END rd_out[212]
  PIN rd_out[213]
    DIRECTION OUTPUT ;
    USE SIGNAL ;
    PORT
      LAYER M4 ;
      RECT 0.00000 10.27200 0.03600 10.29600 ;
    END
  END rd_out[213]
  PIN rd_out[214]
    DIRECTION OUTPUT ;
    USE SIGNAL ;
    PORT
      LAYER M4 ;
      RECT 0.00000 10.32000 0.03600 10.34400 ;
    END
  END rd_out[214]
  PIN rd_out[215]
    DIRECTION OUTPUT ;
    USE SIGNAL ;
    PORT
      LAYER M4 ;
      RECT 0.00000 10.36800 0.03600 10.39200 ;
    END
  END rd_out[215]
  PIN rd_out[216]
    DIRECTION OUTPUT ;
    USE SIGNAL ;
    PORT
      LAYER M4 ;
      RECT 0.00000 10.41600 0.03600 10.44000 ;
    END
  END rd_out[216]
  PIN rd_out[217]
    DIRECTION OUTPUT ;
    USE SIGNAL ;
    PORT
      LAYER M4 ;
      RECT 0.00000 10.46400 0.03600 10.48800 ;
    END
  END rd_out[217]
  PIN rd_out[218]
    DIRECTION OUTPUT ;
    USE SIGNAL ;
    PORT
      LAYER M4 ;
      RECT 0.00000 10.51200 0.03600 10.53600 ;
    END
  END rd_out[218]
  PIN rd_out[219]
    DIRECTION OUTPUT ;
    USE SIGNAL ;
    PORT
      LAYER M4 ;
      RECT 0.00000 10.56000 0.03600 10.58400 ;
    END
  END rd_out[219]
  PIN rd_out[220]
    DIRECTION OUTPUT ;
    USE SIGNAL ;
    PORT
      LAYER M4 ;
      RECT 0.00000 10.60800 0.03600 10.63200 ;
    END
  END rd_out[220]
  PIN rd_out[221]
    DIRECTION OUTPUT ;
    USE SIGNAL ;
    PORT
      LAYER M4 ;
      RECT 0.00000 10.65600 0.03600 10.68000 ;
    END
  END rd_out[221]
  PIN rd_out[222]
    DIRECTION OUTPUT ;
    USE SIGNAL ;
    PORT
      LAYER M4 ;
      RECT 0.00000 10.70400 0.03600 10.72800 ;
    END
  END rd_out[222]
  PIN rd_out[223]
    DIRECTION OUTPUT ;
    USE SIGNAL ;
    PORT
      LAYER M4 ;
      RECT 0.00000 10.75200 0.03600 10.77600 ;
    END
  END rd_out[223]
  PIN rd_out[224]
    DIRECTION OUTPUT ;
    USE SIGNAL ;
    PORT
      LAYER M4 ;
      RECT 0.00000 10.80000 0.03600 10.82400 ;
    END
  END rd_out[224]
  PIN rd_out[225]
    DIRECTION OUTPUT ;
    USE SIGNAL ;
    PORT
      LAYER M4 ;
      RECT 0.00000 10.84800 0.03600 10.87200 ;
    END
  END rd_out[225]
  PIN rd_out[226]
    DIRECTION OUTPUT ;
    USE SIGNAL ;
    PORT
      LAYER M4 ;
      RECT 0.00000 10.89600 0.03600 10.92000 ;
    END
  END rd_out[226]
  PIN rd_out[227]
    DIRECTION OUTPUT ;
    USE SIGNAL ;
    PORT
      LAYER M4 ;
      RECT 0.00000 10.94400 0.03600 10.96800 ;
    END
  END rd_out[227]
  PIN rd_out[228]
    DIRECTION OUTPUT ;
    USE SIGNAL ;
    PORT
      LAYER M4 ;
      RECT 0.00000 10.99200 0.03600 11.01600 ;
    END
  END rd_out[228]
  PIN rd_out[229]
    DIRECTION OUTPUT ;
    USE SIGNAL ;
    PORT
      LAYER M4 ;
      RECT 0.00000 11.04000 0.03600 11.06400 ;
    END
  END rd_out[229]
  PIN rd_out[230]
    DIRECTION OUTPUT ;
    USE SIGNAL ;
    PORT
      LAYER M4 ;
      RECT 0.00000 11.08800 0.03600 11.11200 ;
    END
  END rd_out[230]
  PIN rd_out[231]
    DIRECTION OUTPUT ;
    USE SIGNAL ;
    PORT
      LAYER M4 ;
      RECT 0.00000 11.13600 0.03600 11.16000 ;
    END
  END rd_out[231]
  PIN rd_out[232]
    DIRECTION OUTPUT ;
    USE SIGNAL ;
    PORT
      LAYER M4 ;
      RECT 0.00000 11.18400 0.03600 11.20800 ;
    END
  END rd_out[232]
  PIN rd_out[233]
    DIRECTION OUTPUT ;
    USE SIGNAL ;
    PORT
      LAYER M4 ;
      RECT 0.00000 11.23200 0.03600 11.25600 ;
    END
  END rd_out[233]
  PIN rd_out[234]
    DIRECTION OUTPUT ;
    USE SIGNAL ;
    PORT
      LAYER M4 ;
      RECT 0.00000 11.28000 0.03600 11.30400 ;
    END
  END rd_out[234]
  PIN rd_out[235]
    DIRECTION OUTPUT ;
    USE SIGNAL ;
    PORT
      LAYER M4 ;
      RECT 0.00000 11.32800 0.03600 11.35200 ;
    END
  END rd_out[235]
  PIN rd_out[236]
    DIRECTION OUTPUT ;
    USE SIGNAL ;
    PORT
      LAYER M4 ;
      RECT 0.00000 11.37600 0.03600 11.40000 ;
    END
  END rd_out[236]
  PIN rd_out[237]
    DIRECTION OUTPUT ;
    USE SIGNAL ;
    PORT
      LAYER M4 ;
      RECT 0.00000 11.42400 0.03600 11.44800 ;
    END
  END rd_out[237]
  PIN rd_out[238]
    DIRECTION OUTPUT ;
    USE SIGNAL ;
    PORT
      LAYER M4 ;
      RECT 0.00000 11.47200 0.03600 11.49600 ;
    END
  END rd_out[238]
  PIN rd_out[239]
    DIRECTION OUTPUT ;
    USE SIGNAL ;
    PORT
      LAYER M4 ;
      RECT 0.00000 11.52000 0.03600 11.54400 ;
    END
  END rd_out[239]
  PIN rd_out[240]
    DIRECTION OUTPUT ;
    USE SIGNAL ;
    PORT
      LAYER M4 ;
      RECT 0.00000 11.56800 0.03600 11.59200 ;
    END
  END rd_out[240]
  PIN rd_out[241]
    DIRECTION OUTPUT ;
    USE SIGNAL ;
    PORT
      LAYER M4 ;
      RECT 0.00000 11.61600 0.03600 11.64000 ;
    END
  END rd_out[241]
  PIN rd_out[242]
    DIRECTION OUTPUT ;
    USE SIGNAL ;
    PORT
      LAYER M4 ;
      RECT 0.00000 11.66400 0.03600 11.68800 ;
    END
  END rd_out[242]
  PIN rd_out[243]
    DIRECTION OUTPUT ;
    USE SIGNAL ;
    PORT
      LAYER M4 ;
      RECT 0.00000 11.71200 0.03600 11.73600 ;
    END
  END rd_out[243]
  PIN rd_out[244]
    DIRECTION OUTPUT ;
    USE SIGNAL ;
    PORT
      LAYER M4 ;
      RECT 0.00000 11.76000 0.03600 11.78400 ;
    END
  END rd_out[244]
  PIN rd_out[245]
    DIRECTION OUTPUT ;
    USE SIGNAL ;
    PORT
      LAYER M4 ;
      RECT 0.00000 11.80800 0.03600 11.83200 ;
    END
  END rd_out[245]
  PIN rd_out[246]
    DIRECTION OUTPUT ;
    USE SIGNAL ;
    PORT
      LAYER M4 ;
      RECT 0.00000 11.85600 0.03600 11.88000 ;
    END
  END rd_out[246]
  PIN rd_out[247]
    DIRECTION OUTPUT ;
    USE SIGNAL ;
    PORT
      LAYER M4 ;
      RECT 0.00000 11.90400 0.03600 11.92800 ;
    END
  END rd_out[247]
  PIN rd_out[248]
    DIRECTION OUTPUT ;
    USE SIGNAL ;
    PORT
      LAYER M4 ;
      RECT 0.00000 11.95200 0.03600 11.97600 ;
    END
  END rd_out[248]
  PIN rd_out[249]
    DIRECTION OUTPUT ;
    USE SIGNAL ;
    PORT
      LAYER M4 ;
      RECT 0.00000 12.00000 0.03600 12.02400 ;
    END
  END rd_out[249]
  PIN rd_out[250]
    DIRECTION OUTPUT ;
    USE SIGNAL ;
    PORT
      LAYER M4 ;
      RECT 0.00000 12.04800 0.03600 12.07200 ;
    END
  END rd_out[250]
  PIN rd_out[251]
    DIRECTION OUTPUT ;
    USE SIGNAL ;
    PORT
      LAYER M4 ;
      RECT 0.00000 12.09600 0.03600 12.12000 ;
    END
  END rd_out[251]
  PIN rd_out[252]
    DIRECTION OUTPUT ;
    USE SIGNAL ;
    PORT
      LAYER M4 ;
      RECT 0.00000 12.14400 0.03600 12.16800 ;
    END
  END rd_out[252]
  PIN rd_out[253]
    DIRECTION OUTPUT ;
    USE SIGNAL ;
    PORT
      LAYER M4 ;
      RECT 0.00000 12.19200 0.03600 12.21600 ;
    END
  END rd_out[253]
  PIN rd_out[254]
    DIRECTION OUTPUT ;
    USE SIGNAL ;
    PORT
      LAYER M4 ;
      RECT 0.00000 12.24000 0.03600 12.26400 ;
    END
  END rd_out[254]
  PIN rd_out[255]
    DIRECTION OUTPUT ;
    USE SIGNAL ;
    PORT
      LAYER M4 ;
      RECT 0.00000 12.28800 0.03600 12.31200 ;
    END
  END rd_out[255]
  PIN wd_in[0]
    DIRECTION INPUT ;
    USE SIGNAL ;
    PORT
      LAYER M4 ;
      RECT 0.00000 12.33600 0.03600 12.36000 ;
    END
  END wd_in[0]
  PIN wd_in[1]
    DIRECTION INPUT ;
    USE SIGNAL ;
    PORT
      LAYER M4 ;
      RECT 0.00000 12.38400 0.03600 12.40800 ;
    END
  END wd_in[1]
  PIN wd_in[2]
    DIRECTION INPUT ;
    USE SIGNAL ;
    PORT
      LAYER M4 ;
      RECT 0.00000 12.43200 0.03600 12.45600 ;
    END
  END wd_in[2]
  PIN wd_in[3]
    DIRECTION INPUT ;
    USE SIGNAL ;
    PORT
      LAYER M4 ;
      RECT 0.00000 12.48000 0.03600 12.50400 ;
    END
  END wd_in[3]
  PIN wd_in[4]
    DIRECTION INPUT ;
    USE SIGNAL ;
    PORT
      LAYER M4 ;
      RECT 0.00000 12.52800 0.03600 12.55200 ;
    END
  END wd_in[4]
  PIN wd_in[5]
    DIRECTION INPUT ;
    USE SIGNAL ;
    PORT
      LAYER M4 ;
      RECT 0.00000 12.57600 0.03600 12.60000 ;
    END
  END wd_in[5]
  PIN wd_in[6]
    DIRECTION INPUT ;
    USE SIGNAL ;
    PORT
      LAYER M4 ;
      RECT 0.00000 12.62400 0.03600 12.64800 ;
    END
  END wd_in[6]
  PIN wd_in[7]
    DIRECTION INPUT ;
    USE SIGNAL ;
    PORT
      LAYER M4 ;
      RECT 0.00000 12.67200 0.03600 12.69600 ;
    END
  END wd_in[7]
  PIN wd_in[8]
    DIRECTION INPUT ;
    USE SIGNAL ;
    PORT
      LAYER M4 ;
      RECT 0.00000 12.72000 0.03600 12.74400 ;
    END
  END wd_in[8]
  PIN wd_in[9]
    DIRECTION INPUT ;
    USE SIGNAL ;
    PORT
      LAYER M4 ;
      RECT 0.00000 12.76800 0.03600 12.79200 ;
    END
  END wd_in[9]
  PIN wd_in[10]
    DIRECTION INPUT ;
    USE SIGNAL ;
    PORT
      LAYER M4 ;
      RECT 0.00000 12.81600 0.03600 12.84000 ;
    END
  END wd_in[10]
  PIN wd_in[11]
    DIRECTION INPUT ;
    USE SIGNAL ;
    PORT
      LAYER M4 ;
      RECT 0.00000 12.86400 0.03600 12.88800 ;
    END
  END wd_in[11]
  PIN wd_in[12]
    DIRECTION INPUT ;
    USE SIGNAL ;
    PORT
      LAYER M4 ;
      RECT 0.00000 12.91200 0.03600 12.93600 ;
    END
  END wd_in[12]
  PIN wd_in[13]
    DIRECTION INPUT ;
    USE SIGNAL ;
    PORT
      LAYER M4 ;
      RECT 0.00000 12.96000 0.03600 12.98400 ;
    END
  END wd_in[13]
  PIN wd_in[14]
    DIRECTION INPUT ;
    USE SIGNAL ;
    PORT
      LAYER M4 ;
      RECT 0.00000 13.00800 0.03600 13.03200 ;
    END
  END wd_in[14]
  PIN wd_in[15]
    DIRECTION INPUT ;
    USE SIGNAL ;
    PORT
      LAYER M4 ;
      RECT 0.00000 13.05600 0.03600 13.08000 ;
    END
  END wd_in[15]
  PIN wd_in[16]
    DIRECTION INPUT ;
    USE SIGNAL ;
    PORT
      LAYER M4 ;
      RECT 0.00000 13.10400 0.03600 13.12800 ;
    END
  END wd_in[16]
  PIN wd_in[17]
    DIRECTION INPUT ;
    USE SIGNAL ;
    PORT
      LAYER M4 ;
      RECT 0.00000 13.15200 0.03600 13.17600 ;
    END
  END wd_in[17]
  PIN wd_in[18]
    DIRECTION INPUT ;
    USE SIGNAL ;
    PORT
      LAYER M4 ;
      RECT 0.00000 13.20000 0.03600 13.22400 ;
    END
  END wd_in[18]
  PIN wd_in[19]
    DIRECTION INPUT ;
    USE SIGNAL ;
    PORT
      LAYER M4 ;
      RECT 0.00000 13.24800 0.03600 13.27200 ;
    END
  END wd_in[19]
  PIN wd_in[20]
    DIRECTION INPUT ;
    USE SIGNAL ;
    PORT
      LAYER M4 ;
      RECT 0.00000 13.29600 0.03600 13.32000 ;
    END
  END wd_in[20]
  PIN wd_in[21]
    DIRECTION INPUT ;
    USE SIGNAL ;
    PORT
      LAYER M4 ;
      RECT 0.00000 13.34400 0.03600 13.36800 ;
    END
  END wd_in[21]
  PIN wd_in[22]
    DIRECTION INPUT ;
    USE SIGNAL ;
    PORT
      LAYER M4 ;
      RECT 0.00000 13.39200 0.03600 13.41600 ;
    END
  END wd_in[22]
  PIN wd_in[23]
    DIRECTION INPUT ;
    USE SIGNAL ;
    PORT
      LAYER M4 ;
      RECT 0.00000 13.44000 0.03600 13.46400 ;
    END
  END wd_in[23]
  PIN wd_in[24]
    DIRECTION INPUT ;
    USE SIGNAL ;
    PORT
      LAYER M4 ;
      RECT 0.00000 13.48800 0.03600 13.51200 ;
    END
  END wd_in[24]
  PIN wd_in[25]
    DIRECTION INPUT ;
    USE SIGNAL ;
    PORT
      LAYER M4 ;
      RECT 0.00000 13.53600 0.03600 13.56000 ;
    END
  END wd_in[25]
  PIN wd_in[26]
    DIRECTION INPUT ;
    USE SIGNAL ;
    PORT
      LAYER M4 ;
      RECT 0.00000 13.58400 0.03600 13.60800 ;
    END
  END wd_in[26]
  PIN wd_in[27]
    DIRECTION INPUT ;
    USE SIGNAL ;
    PORT
      LAYER M4 ;
      RECT 0.00000 13.63200 0.03600 13.65600 ;
    END
  END wd_in[27]
  PIN wd_in[28]
    DIRECTION INPUT ;
    USE SIGNAL ;
    PORT
      LAYER M4 ;
      RECT 0.00000 13.68000 0.03600 13.70400 ;
    END
  END wd_in[28]
  PIN wd_in[29]
    DIRECTION INPUT ;
    USE SIGNAL ;
    PORT
      LAYER M4 ;
      RECT 0.00000 13.72800 0.03600 13.75200 ;
    END
  END wd_in[29]
  PIN wd_in[30]
    DIRECTION INPUT ;
    USE SIGNAL ;
    PORT
      LAYER M4 ;
      RECT 0.00000 13.77600 0.03600 13.80000 ;
    END
  END wd_in[30]
  PIN wd_in[31]
    DIRECTION INPUT ;
    USE SIGNAL ;
    PORT
      LAYER M4 ;
      RECT 0.00000 13.82400 0.03600 13.84800 ;
    END
  END wd_in[31]
  PIN wd_in[32]
    DIRECTION INPUT ;
    USE SIGNAL ;
    PORT
      LAYER M4 ;
      RECT 0.00000 13.87200 0.03600 13.89600 ;
    END
  END wd_in[32]
  PIN wd_in[33]
    DIRECTION INPUT ;
    USE SIGNAL ;
    PORT
      LAYER M4 ;
      RECT 0.00000 13.92000 0.03600 13.94400 ;
    END
  END wd_in[33]
  PIN wd_in[34]
    DIRECTION INPUT ;
    USE SIGNAL ;
    PORT
      LAYER M4 ;
      RECT 0.00000 13.96800 0.03600 13.99200 ;
    END
  END wd_in[34]
  PIN wd_in[35]
    DIRECTION INPUT ;
    USE SIGNAL ;
    PORT
      LAYER M4 ;
      RECT 0.00000 14.01600 0.03600 14.04000 ;
    END
  END wd_in[35]
  PIN wd_in[36]
    DIRECTION INPUT ;
    USE SIGNAL ;
    PORT
      LAYER M4 ;
      RECT 0.00000 14.06400 0.03600 14.08800 ;
    END
  END wd_in[36]
  PIN wd_in[37]
    DIRECTION INPUT ;
    USE SIGNAL ;
    PORT
      LAYER M4 ;
      RECT 0.00000 14.11200 0.03600 14.13600 ;
    END
  END wd_in[37]
  PIN wd_in[38]
    DIRECTION INPUT ;
    USE SIGNAL ;
    PORT
      LAYER M4 ;
      RECT 0.00000 14.16000 0.03600 14.18400 ;
    END
  END wd_in[38]
  PIN wd_in[39]
    DIRECTION INPUT ;
    USE SIGNAL ;
    PORT
      LAYER M4 ;
      RECT 0.00000 14.20800 0.03600 14.23200 ;
    END
  END wd_in[39]
  PIN wd_in[40]
    DIRECTION INPUT ;
    USE SIGNAL ;
    PORT
      LAYER M4 ;
      RECT 0.00000 14.25600 0.03600 14.28000 ;
    END
  END wd_in[40]
  PIN wd_in[41]
    DIRECTION INPUT ;
    USE SIGNAL ;
    PORT
      LAYER M4 ;
      RECT 0.00000 14.30400 0.03600 14.32800 ;
    END
  END wd_in[41]
  PIN wd_in[42]
    DIRECTION INPUT ;
    USE SIGNAL ;
    PORT
      LAYER M4 ;
      RECT 0.00000 14.35200 0.03600 14.37600 ;
    END
  END wd_in[42]
  PIN wd_in[43]
    DIRECTION INPUT ;
    USE SIGNAL ;
    PORT
      LAYER M4 ;
      RECT 0.00000 14.40000 0.03600 14.42400 ;
    END
  END wd_in[43]
  PIN wd_in[44]
    DIRECTION INPUT ;
    USE SIGNAL ;
    PORT
      LAYER M4 ;
      RECT 0.00000 14.44800 0.03600 14.47200 ;
    END
  END wd_in[44]
  PIN wd_in[45]
    DIRECTION INPUT ;
    USE SIGNAL ;
    PORT
      LAYER M4 ;
      RECT 0.00000 14.49600 0.03600 14.52000 ;
    END
  END wd_in[45]
  PIN wd_in[46]
    DIRECTION INPUT ;
    USE SIGNAL ;
    PORT
      LAYER M4 ;
      RECT 0.00000 14.54400 0.03600 14.56800 ;
    END
  END wd_in[46]
  PIN wd_in[47]
    DIRECTION INPUT ;
    USE SIGNAL ;
    PORT
      LAYER M4 ;
      RECT 0.00000 14.59200 0.03600 14.61600 ;
    END
  END wd_in[47]
  PIN wd_in[48]
    DIRECTION INPUT ;
    USE SIGNAL ;
    PORT
      LAYER M4 ;
      RECT 0.00000 14.64000 0.03600 14.66400 ;
    END
  END wd_in[48]
  PIN wd_in[49]
    DIRECTION INPUT ;
    USE SIGNAL ;
    PORT
      LAYER M4 ;
      RECT 0.00000 14.68800 0.03600 14.71200 ;
    END
  END wd_in[49]
  PIN wd_in[50]
    DIRECTION INPUT ;
    USE SIGNAL ;
    PORT
      LAYER M4 ;
      RECT 0.00000 14.73600 0.03600 14.76000 ;
    END
  END wd_in[50]
  PIN wd_in[51]
    DIRECTION INPUT ;
    USE SIGNAL ;
    PORT
      LAYER M4 ;
      RECT 0.00000 14.78400 0.03600 14.80800 ;
    END
  END wd_in[51]
  PIN wd_in[52]
    DIRECTION INPUT ;
    USE SIGNAL ;
    PORT
      LAYER M4 ;
      RECT 0.00000 14.83200 0.03600 14.85600 ;
    END
  END wd_in[52]
  PIN wd_in[53]
    DIRECTION INPUT ;
    USE SIGNAL ;
    PORT
      LAYER M4 ;
      RECT 0.00000 14.88000 0.03600 14.90400 ;
    END
  END wd_in[53]
  PIN wd_in[54]
    DIRECTION INPUT ;
    USE SIGNAL ;
    PORT
      LAYER M4 ;
      RECT 0.00000 14.92800 0.03600 14.95200 ;
    END
  END wd_in[54]
  PIN wd_in[55]
    DIRECTION INPUT ;
    USE SIGNAL ;
    PORT
      LAYER M4 ;
      RECT 0.00000 14.97600 0.03600 15.00000 ;
    END
  END wd_in[55]
  PIN wd_in[56]
    DIRECTION INPUT ;
    USE SIGNAL ;
    PORT
      LAYER M4 ;
      RECT 0.00000 15.02400 0.03600 15.04800 ;
    END
  END wd_in[56]
  PIN wd_in[57]
    DIRECTION INPUT ;
    USE SIGNAL ;
    PORT
      LAYER M4 ;
      RECT 0.00000 15.07200 0.03600 15.09600 ;
    END
  END wd_in[57]
  PIN wd_in[58]
    DIRECTION INPUT ;
    USE SIGNAL ;
    PORT
      LAYER M4 ;
      RECT 0.00000 15.12000 0.03600 15.14400 ;
    END
  END wd_in[58]
  PIN wd_in[59]
    DIRECTION INPUT ;
    USE SIGNAL ;
    PORT
      LAYER M4 ;
      RECT 0.00000 15.16800 0.03600 15.19200 ;
    END
  END wd_in[59]
  PIN wd_in[60]
    DIRECTION INPUT ;
    USE SIGNAL ;
    PORT
      LAYER M4 ;
      RECT 0.00000 15.21600 0.03600 15.24000 ;
    END
  END wd_in[60]
  PIN wd_in[61]
    DIRECTION INPUT ;
    USE SIGNAL ;
    PORT
      LAYER M4 ;
      RECT 0.00000 15.26400 0.03600 15.28800 ;
    END
  END wd_in[61]
  PIN wd_in[62]
    DIRECTION INPUT ;
    USE SIGNAL ;
    PORT
      LAYER M4 ;
      RECT 0.00000 15.31200 0.03600 15.33600 ;
    END
  END wd_in[62]
  PIN wd_in[63]
    DIRECTION INPUT ;
    USE SIGNAL ;
    PORT
      LAYER M4 ;
      RECT 0.00000 15.36000 0.03600 15.38400 ;
    END
  END wd_in[63]
  PIN wd_in[64]
    DIRECTION INPUT ;
    USE SIGNAL ;
    PORT
      LAYER M4 ;
      RECT 0.00000 15.40800 0.03600 15.43200 ;
    END
  END wd_in[64]
  PIN wd_in[65]
    DIRECTION INPUT ;
    USE SIGNAL ;
    PORT
      LAYER M4 ;
      RECT 0.00000 15.45600 0.03600 15.48000 ;
    END
  END wd_in[65]
  PIN wd_in[66]
    DIRECTION INPUT ;
    USE SIGNAL ;
    PORT
      LAYER M4 ;
      RECT 0.00000 15.50400 0.03600 15.52800 ;
    END
  END wd_in[66]
  PIN wd_in[67]
    DIRECTION INPUT ;
    USE SIGNAL ;
    PORT
      LAYER M4 ;
      RECT 0.00000 15.55200 0.03600 15.57600 ;
    END
  END wd_in[67]
  PIN wd_in[68]
    DIRECTION INPUT ;
    USE SIGNAL ;
    PORT
      LAYER M4 ;
      RECT 0.00000 15.60000 0.03600 15.62400 ;
    END
  END wd_in[68]
  PIN wd_in[69]
    DIRECTION INPUT ;
    USE SIGNAL ;
    PORT
      LAYER M4 ;
      RECT 0.00000 15.64800 0.03600 15.67200 ;
    END
  END wd_in[69]
  PIN wd_in[70]
    DIRECTION INPUT ;
    USE SIGNAL ;
    PORT
      LAYER M4 ;
      RECT 0.00000 15.69600 0.03600 15.72000 ;
    END
  END wd_in[70]
  PIN wd_in[71]
    DIRECTION INPUT ;
    USE SIGNAL ;
    PORT
      LAYER M4 ;
      RECT 0.00000 15.74400 0.03600 15.76800 ;
    END
  END wd_in[71]
  PIN wd_in[72]
    DIRECTION INPUT ;
    USE SIGNAL ;
    PORT
      LAYER M4 ;
      RECT 0.00000 15.79200 0.03600 15.81600 ;
    END
  END wd_in[72]
  PIN wd_in[73]
    DIRECTION INPUT ;
    USE SIGNAL ;
    PORT
      LAYER M4 ;
      RECT 0.00000 15.84000 0.03600 15.86400 ;
    END
  END wd_in[73]
  PIN wd_in[74]
    DIRECTION INPUT ;
    USE SIGNAL ;
    PORT
      LAYER M4 ;
      RECT 0.00000 15.88800 0.03600 15.91200 ;
    END
  END wd_in[74]
  PIN wd_in[75]
    DIRECTION INPUT ;
    USE SIGNAL ;
    PORT
      LAYER M4 ;
      RECT 0.00000 15.93600 0.03600 15.96000 ;
    END
  END wd_in[75]
  PIN wd_in[76]
    DIRECTION INPUT ;
    USE SIGNAL ;
    PORT
      LAYER M4 ;
      RECT 0.00000 15.98400 0.03600 16.00800 ;
    END
  END wd_in[76]
  PIN wd_in[77]
    DIRECTION INPUT ;
    USE SIGNAL ;
    PORT
      LAYER M4 ;
      RECT 0.00000 16.03200 0.03600 16.05600 ;
    END
  END wd_in[77]
  PIN wd_in[78]
    DIRECTION INPUT ;
    USE SIGNAL ;
    PORT
      LAYER M4 ;
      RECT 0.00000 16.08000 0.03600 16.10400 ;
    END
  END wd_in[78]
  PIN wd_in[79]
    DIRECTION INPUT ;
    USE SIGNAL ;
    PORT
      LAYER M4 ;
      RECT 0.00000 16.12800 0.03600 16.15200 ;
    END
  END wd_in[79]
  PIN wd_in[80]
    DIRECTION INPUT ;
    USE SIGNAL ;
    PORT
      LAYER M4 ;
      RECT 0.00000 16.17600 0.03600 16.20000 ;
    END
  END wd_in[80]
  PIN wd_in[81]
    DIRECTION INPUT ;
    USE SIGNAL ;
    PORT
      LAYER M4 ;
      RECT 0.00000 16.22400 0.03600 16.24800 ;
    END
  END wd_in[81]
  PIN wd_in[82]
    DIRECTION INPUT ;
    USE SIGNAL ;
    PORT
      LAYER M4 ;
      RECT 0.00000 16.27200 0.03600 16.29600 ;
    END
  END wd_in[82]
  PIN wd_in[83]
    DIRECTION INPUT ;
    USE SIGNAL ;
    PORT
      LAYER M4 ;
      RECT 0.00000 16.32000 0.03600 16.34400 ;
    END
  END wd_in[83]
  PIN wd_in[84]
    DIRECTION INPUT ;
    USE SIGNAL ;
    PORT
      LAYER M4 ;
      RECT 0.00000 16.36800 0.03600 16.39200 ;
    END
  END wd_in[84]
  PIN wd_in[85]
    DIRECTION INPUT ;
    USE SIGNAL ;
    PORT
      LAYER M4 ;
      RECT 0.00000 16.41600 0.03600 16.44000 ;
    END
  END wd_in[85]
  PIN wd_in[86]
    DIRECTION INPUT ;
    USE SIGNAL ;
    PORT
      LAYER M4 ;
      RECT 0.00000 16.46400 0.03600 16.48800 ;
    END
  END wd_in[86]
  PIN wd_in[87]
    DIRECTION INPUT ;
    USE SIGNAL ;
    PORT
      LAYER M4 ;
      RECT 0.00000 16.51200 0.03600 16.53600 ;
    END
  END wd_in[87]
  PIN wd_in[88]
    DIRECTION INPUT ;
    USE SIGNAL ;
    PORT
      LAYER M4 ;
      RECT 0.00000 16.56000 0.03600 16.58400 ;
    END
  END wd_in[88]
  PIN wd_in[89]
    DIRECTION INPUT ;
    USE SIGNAL ;
    PORT
      LAYER M4 ;
      RECT 0.00000 16.60800 0.03600 16.63200 ;
    END
  END wd_in[89]
  PIN wd_in[90]
    DIRECTION INPUT ;
    USE SIGNAL ;
    PORT
      LAYER M4 ;
      RECT 0.00000 16.65600 0.03600 16.68000 ;
    END
  END wd_in[90]
  PIN wd_in[91]
    DIRECTION INPUT ;
    USE SIGNAL ;
    PORT
      LAYER M4 ;
      RECT 0.00000 16.70400 0.03600 16.72800 ;
    END
  END wd_in[91]
  PIN wd_in[92]
    DIRECTION INPUT ;
    USE SIGNAL ;
    PORT
      LAYER M4 ;
      RECT 0.00000 16.75200 0.03600 16.77600 ;
    END
  END wd_in[92]
  PIN wd_in[93]
    DIRECTION INPUT ;
    USE SIGNAL ;
    PORT
      LAYER M4 ;
      RECT 0.00000 16.80000 0.03600 16.82400 ;
    END
  END wd_in[93]
  PIN wd_in[94]
    DIRECTION INPUT ;
    USE SIGNAL ;
    PORT
      LAYER M4 ;
      RECT 0.00000 16.84800 0.03600 16.87200 ;
    END
  END wd_in[94]
  PIN wd_in[95]
    DIRECTION INPUT ;
    USE SIGNAL ;
    PORT
      LAYER M4 ;
      RECT 0.00000 16.89600 0.03600 16.92000 ;
    END
  END wd_in[95]
  PIN wd_in[96]
    DIRECTION INPUT ;
    USE SIGNAL ;
    PORT
      LAYER M4 ;
      RECT 0.00000 16.94400 0.03600 16.96800 ;
    END
  END wd_in[96]
  PIN wd_in[97]
    DIRECTION INPUT ;
    USE SIGNAL ;
    PORT
      LAYER M4 ;
      RECT 0.00000 16.99200 0.03600 17.01600 ;
    END
  END wd_in[97]
  PIN wd_in[98]
    DIRECTION INPUT ;
    USE SIGNAL ;
    PORT
      LAYER M4 ;
      RECT 0.00000 17.04000 0.03600 17.06400 ;
    END
  END wd_in[98]
  PIN wd_in[99]
    DIRECTION INPUT ;
    USE SIGNAL ;
    PORT
      LAYER M4 ;
      RECT 0.00000 17.08800 0.03600 17.11200 ;
    END
  END wd_in[99]
  PIN wd_in[100]
    DIRECTION INPUT ;
    USE SIGNAL ;
    PORT
      LAYER M4 ;
      RECT 0.00000 17.13600 0.03600 17.16000 ;
    END
  END wd_in[100]
  PIN wd_in[101]
    DIRECTION INPUT ;
    USE SIGNAL ;
    PORT
      LAYER M4 ;
      RECT 0.00000 17.18400 0.03600 17.20800 ;
    END
  END wd_in[101]
  PIN wd_in[102]
    DIRECTION INPUT ;
    USE SIGNAL ;
    PORT
      LAYER M4 ;
      RECT 0.00000 17.23200 0.03600 17.25600 ;
    END
  END wd_in[102]
  PIN wd_in[103]
    DIRECTION INPUT ;
    USE SIGNAL ;
    PORT
      LAYER M4 ;
      RECT 0.00000 17.28000 0.03600 17.30400 ;
    END
  END wd_in[103]
  PIN wd_in[104]
    DIRECTION INPUT ;
    USE SIGNAL ;
    PORT
      LAYER M4 ;
      RECT 0.00000 17.32800 0.03600 17.35200 ;
    END
  END wd_in[104]
  PIN wd_in[105]
    DIRECTION INPUT ;
    USE SIGNAL ;
    PORT
      LAYER M4 ;
      RECT 0.00000 17.37600 0.03600 17.40000 ;
    END
  END wd_in[105]
  PIN wd_in[106]
    DIRECTION INPUT ;
    USE SIGNAL ;
    PORT
      LAYER M4 ;
      RECT 0.00000 17.42400 0.03600 17.44800 ;
    END
  END wd_in[106]
  PIN wd_in[107]
    DIRECTION INPUT ;
    USE SIGNAL ;
    PORT
      LAYER M4 ;
      RECT 0.00000 17.47200 0.03600 17.49600 ;
    END
  END wd_in[107]
  PIN wd_in[108]
    DIRECTION INPUT ;
    USE SIGNAL ;
    PORT
      LAYER M4 ;
      RECT 0.00000 17.52000 0.03600 17.54400 ;
    END
  END wd_in[108]
  PIN wd_in[109]
    DIRECTION INPUT ;
    USE SIGNAL ;
    PORT
      LAYER M4 ;
      RECT 0.00000 17.56800 0.03600 17.59200 ;
    END
  END wd_in[109]
  PIN wd_in[110]
    DIRECTION INPUT ;
    USE SIGNAL ;
    PORT
      LAYER M4 ;
      RECT 0.00000 17.61600 0.03600 17.64000 ;
    END
  END wd_in[110]
  PIN wd_in[111]
    DIRECTION INPUT ;
    USE SIGNAL ;
    PORT
      LAYER M4 ;
      RECT 0.00000 17.66400 0.03600 17.68800 ;
    END
  END wd_in[111]
  PIN wd_in[112]
    DIRECTION INPUT ;
    USE SIGNAL ;
    PORT
      LAYER M4 ;
      RECT 0.00000 17.71200 0.03600 17.73600 ;
    END
  END wd_in[112]
  PIN wd_in[113]
    DIRECTION INPUT ;
    USE SIGNAL ;
    PORT
      LAYER M4 ;
      RECT 0.00000 17.76000 0.03600 17.78400 ;
    END
  END wd_in[113]
  PIN wd_in[114]
    DIRECTION INPUT ;
    USE SIGNAL ;
    PORT
      LAYER M4 ;
      RECT 0.00000 17.80800 0.03600 17.83200 ;
    END
  END wd_in[114]
  PIN wd_in[115]
    DIRECTION INPUT ;
    USE SIGNAL ;
    PORT
      LAYER M4 ;
      RECT 0.00000 17.85600 0.03600 17.88000 ;
    END
  END wd_in[115]
  PIN wd_in[116]
    DIRECTION INPUT ;
    USE SIGNAL ;
    PORT
      LAYER M4 ;
      RECT 0.00000 17.90400 0.03600 17.92800 ;
    END
  END wd_in[116]
  PIN wd_in[117]
    DIRECTION INPUT ;
    USE SIGNAL ;
    PORT
      LAYER M4 ;
      RECT 0.00000 17.95200 0.03600 17.97600 ;
    END
  END wd_in[117]
  PIN wd_in[118]
    DIRECTION INPUT ;
    USE SIGNAL ;
    PORT
      LAYER M4 ;
      RECT 0.00000 18.00000 0.03600 18.02400 ;
    END
  END wd_in[118]
  PIN wd_in[119]
    DIRECTION INPUT ;
    USE SIGNAL ;
    PORT
      LAYER M4 ;
      RECT 0.00000 18.04800 0.03600 18.07200 ;
    END
  END wd_in[119]
  PIN wd_in[120]
    DIRECTION INPUT ;
    USE SIGNAL ;
    PORT
      LAYER M4 ;
      RECT 0.00000 18.09600 0.03600 18.12000 ;
    END
  END wd_in[120]
  PIN wd_in[121]
    DIRECTION INPUT ;
    USE SIGNAL ;
    PORT
      LAYER M4 ;
      RECT 0.00000 18.14400 0.03600 18.16800 ;
    END
  END wd_in[121]
  PIN wd_in[122]
    DIRECTION INPUT ;
    USE SIGNAL ;
    PORT
      LAYER M4 ;
      RECT 0.00000 18.19200 0.03600 18.21600 ;
    END
  END wd_in[122]
  PIN wd_in[123]
    DIRECTION INPUT ;
    USE SIGNAL ;
    PORT
      LAYER M4 ;
      RECT 0.00000 18.24000 0.03600 18.26400 ;
    END
  END wd_in[123]
  PIN wd_in[124]
    DIRECTION INPUT ;
    USE SIGNAL ;
    PORT
      LAYER M4 ;
      RECT 0.00000 18.28800 0.03600 18.31200 ;
    END
  END wd_in[124]
  PIN wd_in[125]
    DIRECTION INPUT ;
    USE SIGNAL ;
    PORT
      LAYER M4 ;
      RECT 0.00000 18.33600 0.03600 18.36000 ;
    END
  END wd_in[125]
  PIN wd_in[126]
    DIRECTION INPUT ;
    USE SIGNAL ;
    PORT
      LAYER M4 ;
      RECT 0.00000 18.38400 0.03600 18.40800 ;
    END
  END wd_in[126]
  PIN wd_in[127]
    DIRECTION INPUT ;
    USE SIGNAL ;
    PORT
      LAYER M4 ;
      RECT 0.00000 18.43200 0.03600 18.45600 ;
    END
  END wd_in[127]
  PIN wd_in[128]
    DIRECTION INPUT ;
    USE SIGNAL ;
    PORT
      LAYER M4 ;
      RECT 0.00000 18.48000 0.03600 18.50400 ;
    END
  END wd_in[128]
  PIN wd_in[129]
    DIRECTION INPUT ;
    USE SIGNAL ;
    PORT
      LAYER M4 ;
      RECT 0.00000 18.52800 0.03600 18.55200 ;
    END
  END wd_in[129]
  PIN wd_in[130]
    DIRECTION INPUT ;
    USE SIGNAL ;
    PORT
      LAYER M4 ;
      RECT 0.00000 18.57600 0.03600 18.60000 ;
    END
  END wd_in[130]
  PIN wd_in[131]
    DIRECTION INPUT ;
    USE SIGNAL ;
    PORT
      LAYER M4 ;
      RECT 0.00000 18.62400 0.03600 18.64800 ;
    END
  END wd_in[131]
  PIN wd_in[132]
    DIRECTION INPUT ;
    USE SIGNAL ;
    PORT
      LAYER M4 ;
      RECT 0.00000 18.67200 0.03600 18.69600 ;
    END
  END wd_in[132]
  PIN wd_in[133]
    DIRECTION INPUT ;
    USE SIGNAL ;
    PORT
      LAYER M4 ;
      RECT 0.00000 18.72000 0.03600 18.74400 ;
    END
  END wd_in[133]
  PIN wd_in[134]
    DIRECTION INPUT ;
    USE SIGNAL ;
    PORT
      LAYER M4 ;
      RECT 0.00000 18.76800 0.03600 18.79200 ;
    END
  END wd_in[134]
  PIN wd_in[135]
    DIRECTION INPUT ;
    USE SIGNAL ;
    PORT
      LAYER M4 ;
      RECT 0.00000 18.81600 0.03600 18.84000 ;
    END
  END wd_in[135]
  PIN wd_in[136]
    DIRECTION INPUT ;
    USE SIGNAL ;
    PORT
      LAYER M4 ;
      RECT 0.00000 18.86400 0.03600 18.88800 ;
    END
  END wd_in[136]
  PIN wd_in[137]
    DIRECTION INPUT ;
    USE SIGNAL ;
    PORT
      LAYER M4 ;
      RECT 0.00000 18.91200 0.03600 18.93600 ;
    END
  END wd_in[137]
  PIN wd_in[138]
    DIRECTION INPUT ;
    USE SIGNAL ;
    PORT
      LAYER M4 ;
      RECT 0.00000 18.96000 0.03600 18.98400 ;
    END
  END wd_in[138]
  PIN wd_in[139]
    DIRECTION INPUT ;
    USE SIGNAL ;
    PORT
      LAYER M4 ;
      RECT 0.00000 19.00800 0.03600 19.03200 ;
    END
  END wd_in[139]
  PIN wd_in[140]
    DIRECTION INPUT ;
    USE SIGNAL ;
    PORT
      LAYER M4 ;
      RECT 0.00000 19.05600 0.03600 19.08000 ;
    END
  END wd_in[140]
  PIN wd_in[141]
    DIRECTION INPUT ;
    USE SIGNAL ;
    PORT
      LAYER M4 ;
      RECT 0.00000 19.10400 0.03600 19.12800 ;
    END
  END wd_in[141]
  PIN wd_in[142]
    DIRECTION INPUT ;
    USE SIGNAL ;
    PORT
      LAYER M4 ;
      RECT 0.00000 19.15200 0.03600 19.17600 ;
    END
  END wd_in[142]
  PIN wd_in[143]
    DIRECTION INPUT ;
    USE SIGNAL ;
    PORT
      LAYER M4 ;
      RECT 0.00000 19.20000 0.03600 19.22400 ;
    END
  END wd_in[143]
  PIN wd_in[144]
    DIRECTION INPUT ;
    USE SIGNAL ;
    PORT
      LAYER M4 ;
      RECT 0.00000 19.24800 0.03600 19.27200 ;
    END
  END wd_in[144]
  PIN wd_in[145]
    DIRECTION INPUT ;
    USE SIGNAL ;
    PORT
      LAYER M4 ;
      RECT 0.00000 19.29600 0.03600 19.32000 ;
    END
  END wd_in[145]
  PIN wd_in[146]
    DIRECTION INPUT ;
    USE SIGNAL ;
    PORT
      LAYER M4 ;
      RECT 0.00000 19.34400 0.03600 19.36800 ;
    END
  END wd_in[146]
  PIN wd_in[147]
    DIRECTION INPUT ;
    USE SIGNAL ;
    PORT
      LAYER M4 ;
      RECT 0.00000 19.39200 0.03600 19.41600 ;
    END
  END wd_in[147]
  PIN wd_in[148]
    DIRECTION INPUT ;
    USE SIGNAL ;
    PORT
      LAYER M4 ;
      RECT 0.00000 19.44000 0.03600 19.46400 ;
    END
  END wd_in[148]
  PIN wd_in[149]
    DIRECTION INPUT ;
    USE SIGNAL ;
    PORT
      LAYER M4 ;
      RECT 0.00000 19.48800 0.03600 19.51200 ;
    END
  END wd_in[149]
  PIN wd_in[150]
    DIRECTION INPUT ;
    USE SIGNAL ;
    PORT
      LAYER M4 ;
      RECT 0.00000 19.53600 0.03600 19.56000 ;
    END
  END wd_in[150]
  PIN wd_in[151]
    DIRECTION INPUT ;
    USE SIGNAL ;
    PORT
      LAYER M4 ;
      RECT 0.00000 19.58400 0.03600 19.60800 ;
    END
  END wd_in[151]
  PIN wd_in[152]
    DIRECTION INPUT ;
    USE SIGNAL ;
    PORT
      LAYER M4 ;
      RECT 0.00000 19.63200 0.03600 19.65600 ;
    END
  END wd_in[152]
  PIN wd_in[153]
    DIRECTION INPUT ;
    USE SIGNAL ;
    PORT
      LAYER M4 ;
      RECT 0.00000 19.68000 0.03600 19.70400 ;
    END
  END wd_in[153]
  PIN wd_in[154]
    DIRECTION INPUT ;
    USE SIGNAL ;
    PORT
      LAYER M4 ;
      RECT 0.00000 19.72800 0.03600 19.75200 ;
    END
  END wd_in[154]
  PIN wd_in[155]
    DIRECTION INPUT ;
    USE SIGNAL ;
    PORT
      LAYER M4 ;
      RECT 0.00000 19.77600 0.03600 19.80000 ;
    END
  END wd_in[155]
  PIN wd_in[156]
    DIRECTION INPUT ;
    USE SIGNAL ;
    PORT
      LAYER M4 ;
      RECT 0.00000 19.82400 0.03600 19.84800 ;
    END
  END wd_in[156]
  PIN wd_in[157]
    DIRECTION INPUT ;
    USE SIGNAL ;
    PORT
      LAYER M4 ;
      RECT 0.00000 19.87200 0.03600 19.89600 ;
    END
  END wd_in[157]
  PIN wd_in[158]
    DIRECTION INPUT ;
    USE SIGNAL ;
    PORT
      LAYER M4 ;
      RECT 0.00000 19.92000 0.03600 19.94400 ;
    END
  END wd_in[158]
  PIN wd_in[159]
    DIRECTION INPUT ;
    USE SIGNAL ;
    PORT
      LAYER M4 ;
      RECT 0.00000 19.96800 0.03600 19.99200 ;
    END
  END wd_in[159]
  PIN wd_in[160]
    DIRECTION INPUT ;
    USE SIGNAL ;
    PORT
      LAYER M4 ;
      RECT 0.00000 20.01600 0.03600 20.04000 ;
    END
  END wd_in[160]
  PIN wd_in[161]
    DIRECTION INPUT ;
    USE SIGNAL ;
    PORT
      LAYER M4 ;
      RECT 0.00000 20.06400 0.03600 20.08800 ;
    END
  END wd_in[161]
  PIN wd_in[162]
    DIRECTION INPUT ;
    USE SIGNAL ;
    PORT
      LAYER M4 ;
      RECT 0.00000 20.11200 0.03600 20.13600 ;
    END
  END wd_in[162]
  PIN wd_in[163]
    DIRECTION INPUT ;
    USE SIGNAL ;
    PORT
      LAYER M4 ;
      RECT 0.00000 20.16000 0.03600 20.18400 ;
    END
  END wd_in[163]
  PIN wd_in[164]
    DIRECTION INPUT ;
    USE SIGNAL ;
    PORT
      LAYER M4 ;
      RECT 0.00000 20.20800 0.03600 20.23200 ;
    END
  END wd_in[164]
  PIN wd_in[165]
    DIRECTION INPUT ;
    USE SIGNAL ;
    PORT
      LAYER M4 ;
      RECT 0.00000 20.25600 0.03600 20.28000 ;
    END
  END wd_in[165]
  PIN wd_in[166]
    DIRECTION INPUT ;
    USE SIGNAL ;
    PORT
      LAYER M4 ;
      RECT 0.00000 20.30400 0.03600 20.32800 ;
    END
  END wd_in[166]
  PIN wd_in[167]
    DIRECTION INPUT ;
    USE SIGNAL ;
    PORT
      LAYER M4 ;
      RECT 0.00000 20.35200 0.03600 20.37600 ;
    END
  END wd_in[167]
  PIN wd_in[168]
    DIRECTION INPUT ;
    USE SIGNAL ;
    PORT
      LAYER M4 ;
      RECT 0.00000 20.40000 0.03600 20.42400 ;
    END
  END wd_in[168]
  PIN wd_in[169]
    DIRECTION INPUT ;
    USE SIGNAL ;
    PORT
      LAYER M4 ;
      RECT 0.00000 20.44800 0.03600 20.47200 ;
    END
  END wd_in[169]
  PIN wd_in[170]
    DIRECTION INPUT ;
    USE SIGNAL ;
    PORT
      LAYER M4 ;
      RECT 0.00000 20.49600 0.03600 20.52000 ;
    END
  END wd_in[170]
  PIN wd_in[171]
    DIRECTION INPUT ;
    USE SIGNAL ;
    PORT
      LAYER M4 ;
      RECT 0.00000 20.54400 0.03600 20.56800 ;
    END
  END wd_in[171]
  PIN wd_in[172]
    DIRECTION INPUT ;
    USE SIGNAL ;
    PORT
      LAYER M4 ;
      RECT 0.00000 20.59200 0.03600 20.61600 ;
    END
  END wd_in[172]
  PIN wd_in[173]
    DIRECTION INPUT ;
    USE SIGNAL ;
    PORT
      LAYER M4 ;
      RECT 0.00000 20.64000 0.03600 20.66400 ;
    END
  END wd_in[173]
  PIN wd_in[174]
    DIRECTION INPUT ;
    USE SIGNAL ;
    PORT
      LAYER M4 ;
      RECT 0.00000 20.68800 0.03600 20.71200 ;
    END
  END wd_in[174]
  PIN wd_in[175]
    DIRECTION INPUT ;
    USE SIGNAL ;
    PORT
      LAYER M4 ;
      RECT 0.00000 20.73600 0.03600 20.76000 ;
    END
  END wd_in[175]
  PIN wd_in[176]
    DIRECTION INPUT ;
    USE SIGNAL ;
    PORT
      LAYER M4 ;
      RECT 0.00000 20.78400 0.03600 20.80800 ;
    END
  END wd_in[176]
  PIN wd_in[177]
    DIRECTION INPUT ;
    USE SIGNAL ;
    PORT
      LAYER M4 ;
      RECT 0.00000 20.83200 0.03600 20.85600 ;
    END
  END wd_in[177]
  PIN wd_in[178]
    DIRECTION INPUT ;
    USE SIGNAL ;
    PORT
      LAYER M4 ;
      RECT 0.00000 20.88000 0.03600 20.90400 ;
    END
  END wd_in[178]
  PIN wd_in[179]
    DIRECTION INPUT ;
    USE SIGNAL ;
    PORT
      LAYER M4 ;
      RECT 0.00000 20.92800 0.03600 20.95200 ;
    END
  END wd_in[179]
  PIN wd_in[180]
    DIRECTION INPUT ;
    USE SIGNAL ;
    PORT
      LAYER M4 ;
      RECT 0.00000 20.97600 0.03600 21.00000 ;
    END
  END wd_in[180]
  PIN wd_in[181]
    DIRECTION INPUT ;
    USE SIGNAL ;
    PORT
      LAYER M4 ;
      RECT 0.00000 21.02400 0.03600 21.04800 ;
    END
  END wd_in[181]
  PIN wd_in[182]
    DIRECTION INPUT ;
    USE SIGNAL ;
    PORT
      LAYER M4 ;
      RECT 0.00000 21.07200 0.03600 21.09600 ;
    END
  END wd_in[182]
  PIN wd_in[183]
    DIRECTION INPUT ;
    USE SIGNAL ;
    PORT
      LAYER M4 ;
      RECT 0.00000 21.12000 0.03600 21.14400 ;
    END
  END wd_in[183]
  PIN wd_in[184]
    DIRECTION INPUT ;
    USE SIGNAL ;
    PORT
      LAYER M4 ;
      RECT 0.00000 21.16800 0.03600 21.19200 ;
    END
  END wd_in[184]
  PIN wd_in[185]
    DIRECTION INPUT ;
    USE SIGNAL ;
    PORT
      LAYER M4 ;
      RECT 0.00000 21.21600 0.03600 21.24000 ;
    END
  END wd_in[185]
  PIN wd_in[186]
    DIRECTION INPUT ;
    USE SIGNAL ;
    PORT
      LAYER M4 ;
      RECT 0.00000 21.26400 0.03600 21.28800 ;
    END
  END wd_in[186]
  PIN wd_in[187]
    DIRECTION INPUT ;
    USE SIGNAL ;
    PORT
      LAYER M4 ;
      RECT 0.00000 21.31200 0.03600 21.33600 ;
    END
  END wd_in[187]
  PIN wd_in[188]
    DIRECTION INPUT ;
    USE SIGNAL ;
    PORT
      LAYER M4 ;
      RECT 0.00000 21.36000 0.03600 21.38400 ;
    END
  END wd_in[188]
  PIN wd_in[189]
    DIRECTION INPUT ;
    USE SIGNAL ;
    PORT
      LAYER M4 ;
      RECT 0.00000 21.40800 0.03600 21.43200 ;
    END
  END wd_in[189]
  PIN wd_in[190]
    DIRECTION INPUT ;
    USE SIGNAL ;
    PORT
      LAYER M4 ;
      RECT 0.00000 21.45600 0.03600 21.48000 ;
    END
  END wd_in[190]
  PIN wd_in[191]
    DIRECTION INPUT ;
    USE SIGNAL ;
    PORT
      LAYER M4 ;
      RECT 0.00000 21.50400 0.03600 21.52800 ;
    END
  END wd_in[191]
  PIN wd_in[192]
    DIRECTION INPUT ;
    USE SIGNAL ;
    PORT
      LAYER M4 ;
      RECT 0.00000 21.55200 0.03600 21.57600 ;
    END
  END wd_in[192]
  PIN wd_in[193]
    DIRECTION INPUT ;
    USE SIGNAL ;
    PORT
      LAYER M4 ;
      RECT 0.00000 21.60000 0.03600 21.62400 ;
    END
  END wd_in[193]
  PIN wd_in[194]
    DIRECTION INPUT ;
    USE SIGNAL ;
    PORT
      LAYER M4 ;
      RECT 0.00000 21.64800 0.03600 21.67200 ;
    END
  END wd_in[194]
  PIN wd_in[195]
    DIRECTION INPUT ;
    USE SIGNAL ;
    PORT
      LAYER M4 ;
      RECT 0.00000 21.69600 0.03600 21.72000 ;
    END
  END wd_in[195]
  PIN wd_in[196]
    DIRECTION INPUT ;
    USE SIGNAL ;
    PORT
      LAYER M4 ;
      RECT 0.00000 21.74400 0.03600 21.76800 ;
    END
  END wd_in[196]
  PIN wd_in[197]
    DIRECTION INPUT ;
    USE SIGNAL ;
    PORT
      LAYER M4 ;
      RECT 0.00000 21.79200 0.03600 21.81600 ;
    END
  END wd_in[197]
  PIN wd_in[198]
    DIRECTION INPUT ;
    USE SIGNAL ;
    PORT
      LAYER M4 ;
      RECT 0.00000 21.84000 0.03600 21.86400 ;
    END
  END wd_in[198]
  PIN wd_in[199]
    DIRECTION INPUT ;
    USE SIGNAL ;
    PORT
      LAYER M4 ;
      RECT 0.00000 21.88800 0.03600 21.91200 ;
    END
  END wd_in[199]
  PIN wd_in[200]
    DIRECTION INPUT ;
    USE SIGNAL ;
    PORT
      LAYER M4 ;
      RECT 0.00000 21.93600 0.03600 21.96000 ;
    END
  END wd_in[200]
  PIN wd_in[201]
    DIRECTION INPUT ;
    USE SIGNAL ;
    PORT
      LAYER M4 ;
      RECT 0.00000 21.98400 0.03600 22.00800 ;
    END
  END wd_in[201]
  PIN wd_in[202]
    DIRECTION INPUT ;
    USE SIGNAL ;
    PORT
      LAYER M4 ;
      RECT 0.00000 22.03200 0.03600 22.05600 ;
    END
  END wd_in[202]
  PIN wd_in[203]
    DIRECTION INPUT ;
    USE SIGNAL ;
    PORT
      LAYER M4 ;
      RECT 0.00000 22.08000 0.03600 22.10400 ;
    END
  END wd_in[203]
  PIN wd_in[204]
    DIRECTION INPUT ;
    USE SIGNAL ;
    PORT
      LAYER M4 ;
      RECT 0.00000 22.12800 0.03600 22.15200 ;
    END
  END wd_in[204]
  PIN wd_in[205]
    DIRECTION INPUT ;
    USE SIGNAL ;
    PORT
      LAYER M4 ;
      RECT 0.00000 22.17600 0.03600 22.20000 ;
    END
  END wd_in[205]
  PIN wd_in[206]
    DIRECTION INPUT ;
    USE SIGNAL ;
    PORT
      LAYER M4 ;
      RECT 0.00000 22.22400 0.03600 22.24800 ;
    END
  END wd_in[206]
  PIN wd_in[207]
    DIRECTION INPUT ;
    USE SIGNAL ;
    PORT
      LAYER M4 ;
      RECT 0.00000 22.27200 0.03600 22.29600 ;
    END
  END wd_in[207]
  PIN wd_in[208]
    DIRECTION INPUT ;
    USE SIGNAL ;
    PORT
      LAYER M4 ;
      RECT 0.00000 22.32000 0.03600 22.34400 ;
    END
  END wd_in[208]
  PIN wd_in[209]
    DIRECTION INPUT ;
    USE SIGNAL ;
    PORT
      LAYER M4 ;
      RECT 0.00000 22.36800 0.03600 22.39200 ;
    END
  END wd_in[209]
  PIN wd_in[210]
    DIRECTION INPUT ;
    USE SIGNAL ;
    PORT
      LAYER M4 ;
      RECT 0.00000 22.41600 0.03600 22.44000 ;
    END
  END wd_in[210]
  PIN wd_in[211]
    DIRECTION INPUT ;
    USE SIGNAL ;
    PORT
      LAYER M4 ;
      RECT 0.00000 22.46400 0.03600 22.48800 ;
    END
  END wd_in[211]
  PIN wd_in[212]
    DIRECTION INPUT ;
    USE SIGNAL ;
    PORT
      LAYER M4 ;
      RECT 0.00000 22.51200 0.03600 22.53600 ;
    END
  END wd_in[212]
  PIN wd_in[213]
    DIRECTION INPUT ;
    USE SIGNAL ;
    PORT
      LAYER M4 ;
      RECT 0.00000 22.56000 0.03600 22.58400 ;
    END
  END wd_in[213]
  PIN wd_in[214]
    DIRECTION INPUT ;
    USE SIGNAL ;
    PORT
      LAYER M4 ;
      RECT 0.00000 22.60800 0.03600 22.63200 ;
    END
  END wd_in[214]
  PIN wd_in[215]
    DIRECTION INPUT ;
    USE SIGNAL ;
    PORT
      LAYER M4 ;
      RECT 0.00000 22.65600 0.03600 22.68000 ;
    END
  END wd_in[215]
  PIN wd_in[216]
    DIRECTION INPUT ;
    USE SIGNAL ;
    PORT
      LAYER M4 ;
      RECT 0.00000 22.70400 0.03600 22.72800 ;
    END
  END wd_in[216]
  PIN wd_in[217]
    DIRECTION INPUT ;
    USE SIGNAL ;
    PORT
      LAYER M4 ;
      RECT 0.00000 22.75200 0.03600 22.77600 ;
    END
  END wd_in[217]
  PIN wd_in[218]
    DIRECTION INPUT ;
    USE SIGNAL ;
    PORT
      LAYER M4 ;
      RECT 0.00000 22.80000 0.03600 22.82400 ;
    END
  END wd_in[218]
  PIN wd_in[219]
    DIRECTION INPUT ;
    USE SIGNAL ;
    PORT
      LAYER M4 ;
      RECT 0.00000 22.84800 0.03600 22.87200 ;
    END
  END wd_in[219]
  PIN wd_in[220]
    DIRECTION INPUT ;
    USE SIGNAL ;
    PORT
      LAYER M4 ;
      RECT 0.00000 22.89600 0.03600 22.92000 ;
    END
  END wd_in[220]
  PIN wd_in[221]
    DIRECTION INPUT ;
    USE SIGNAL ;
    PORT
      LAYER M4 ;
      RECT 0.00000 22.94400 0.03600 22.96800 ;
    END
  END wd_in[221]
  PIN wd_in[222]
    DIRECTION INPUT ;
    USE SIGNAL ;
    PORT
      LAYER M4 ;
      RECT 0.00000 22.99200 0.03600 23.01600 ;
    END
  END wd_in[222]
  PIN wd_in[223]
    DIRECTION INPUT ;
    USE SIGNAL ;
    PORT
      LAYER M4 ;
      RECT 0.00000 23.04000 0.03600 23.06400 ;
    END
  END wd_in[223]
  PIN wd_in[224]
    DIRECTION INPUT ;
    USE SIGNAL ;
    PORT
      LAYER M4 ;
      RECT 0.00000 23.08800 0.03600 23.11200 ;
    END
  END wd_in[224]
  PIN wd_in[225]
    DIRECTION INPUT ;
    USE SIGNAL ;
    PORT
      LAYER M4 ;
      RECT 0.00000 23.13600 0.03600 23.16000 ;
    END
  END wd_in[225]
  PIN wd_in[226]
    DIRECTION INPUT ;
    USE SIGNAL ;
    PORT
      LAYER M4 ;
      RECT 0.00000 23.18400 0.03600 23.20800 ;
    END
  END wd_in[226]
  PIN wd_in[227]
    DIRECTION INPUT ;
    USE SIGNAL ;
    PORT
      LAYER M4 ;
      RECT 0.00000 23.23200 0.03600 23.25600 ;
    END
  END wd_in[227]
  PIN wd_in[228]
    DIRECTION INPUT ;
    USE SIGNAL ;
    PORT
      LAYER M4 ;
      RECT 0.00000 23.28000 0.03600 23.30400 ;
    END
  END wd_in[228]
  PIN wd_in[229]
    DIRECTION INPUT ;
    USE SIGNAL ;
    PORT
      LAYER M4 ;
      RECT 0.00000 23.32800 0.03600 23.35200 ;
    END
  END wd_in[229]
  PIN wd_in[230]
    DIRECTION INPUT ;
    USE SIGNAL ;
    PORT
      LAYER M4 ;
      RECT 0.00000 23.37600 0.03600 23.40000 ;
    END
  END wd_in[230]
  PIN wd_in[231]
    DIRECTION INPUT ;
    USE SIGNAL ;
    PORT
      LAYER M4 ;
      RECT 0.00000 23.42400 0.03600 23.44800 ;
    END
  END wd_in[231]
  PIN wd_in[232]
    DIRECTION INPUT ;
    USE SIGNAL ;
    PORT
      LAYER M4 ;
      RECT 0.00000 23.47200 0.03600 23.49600 ;
    END
  END wd_in[232]
  PIN wd_in[233]
    DIRECTION INPUT ;
    USE SIGNAL ;
    PORT
      LAYER M4 ;
      RECT 0.00000 23.52000 0.03600 23.54400 ;
    END
  END wd_in[233]
  PIN wd_in[234]
    DIRECTION INPUT ;
    USE SIGNAL ;
    PORT
      LAYER M4 ;
      RECT 0.00000 23.56800 0.03600 23.59200 ;
    END
  END wd_in[234]
  PIN wd_in[235]
    DIRECTION INPUT ;
    USE SIGNAL ;
    PORT
      LAYER M4 ;
      RECT 0.00000 23.61600 0.03600 23.64000 ;
    END
  END wd_in[235]
  PIN wd_in[236]
    DIRECTION INPUT ;
    USE SIGNAL ;
    PORT
      LAYER M4 ;
      RECT 0.00000 23.66400 0.03600 23.68800 ;
    END
  END wd_in[236]
  PIN wd_in[237]
    DIRECTION INPUT ;
    USE SIGNAL ;
    PORT
      LAYER M4 ;
      RECT 0.00000 23.71200 0.03600 23.73600 ;
    END
  END wd_in[237]
  PIN wd_in[238]
    DIRECTION INPUT ;
    USE SIGNAL ;
    PORT
      LAYER M4 ;
      RECT 0.00000 23.76000 0.03600 23.78400 ;
    END
  END wd_in[238]
  PIN wd_in[239]
    DIRECTION INPUT ;
    USE SIGNAL ;
    PORT
      LAYER M4 ;
      RECT 0.00000 23.80800 0.03600 23.83200 ;
    END
  END wd_in[239]
  PIN wd_in[240]
    DIRECTION INPUT ;
    USE SIGNAL ;
    PORT
      LAYER M4 ;
      RECT 0.00000 23.85600 0.03600 23.88000 ;
    END
  END wd_in[240]
  PIN wd_in[241]
    DIRECTION INPUT ;
    USE SIGNAL ;
    PORT
      LAYER M4 ;
      RECT 0.00000 23.90400 0.03600 23.92800 ;
    END
  END wd_in[241]
  PIN wd_in[242]
    DIRECTION INPUT ;
    USE SIGNAL ;
    PORT
      LAYER M4 ;
      RECT 0.00000 23.95200 0.03600 23.97600 ;
    END
  END wd_in[242]
  PIN wd_in[243]
    DIRECTION INPUT ;
    USE SIGNAL ;
    PORT
      LAYER M4 ;
      RECT 0.00000 24.00000 0.03600 24.02400 ;
    END
  END wd_in[243]
  PIN wd_in[244]
    DIRECTION INPUT ;
    USE SIGNAL ;
    PORT
      LAYER M4 ;
      RECT 0.00000 24.04800 0.03600 24.07200 ;
    END
  END wd_in[244]
  PIN wd_in[245]
    DIRECTION INPUT ;
    USE SIGNAL ;
    PORT
      LAYER M4 ;
      RECT 0.00000 24.09600 0.03600 24.12000 ;
    END
  END wd_in[245]
  PIN wd_in[246]
    DIRECTION INPUT ;
    USE SIGNAL ;
    PORT
      LAYER M4 ;
      RECT 0.00000 24.14400 0.03600 24.16800 ;
    END
  END wd_in[246]
  PIN wd_in[247]
    DIRECTION INPUT ;
    USE SIGNAL ;
    PORT
      LAYER M4 ;
      RECT 0.00000 24.19200 0.03600 24.21600 ;
    END
  END wd_in[247]
  PIN wd_in[248]
    DIRECTION INPUT ;
    USE SIGNAL ;
    PORT
      LAYER M4 ;
      RECT 0.00000 24.24000 0.03600 24.26400 ;
    END
  END wd_in[248]
  PIN wd_in[249]
    DIRECTION INPUT ;
    USE SIGNAL ;
    PORT
      LAYER M4 ;
      RECT 0.00000 24.28800 0.03600 24.31200 ;
    END
  END wd_in[249]
  PIN wd_in[250]
    DIRECTION INPUT ;
    USE SIGNAL ;
    PORT
      LAYER M4 ;
      RECT 0.00000 24.33600 0.03600 24.36000 ;
    END
  END wd_in[250]
  PIN wd_in[251]
    DIRECTION INPUT ;
    USE SIGNAL ;
    PORT
      LAYER M4 ;
      RECT 0.00000 24.38400 0.03600 24.40800 ;
    END
  END wd_in[251]
  PIN wd_in[252]
    DIRECTION INPUT ;
    USE SIGNAL ;
    PORT
      LAYER M4 ;
      RECT 0.00000 24.43200 0.03600 24.45600 ;
    END
  END wd_in[252]
  PIN wd_in[253]
    DIRECTION INPUT ;
    USE SIGNAL ;
    PORT
      LAYER M4 ;
      RECT 0.00000 24.48000 0.03600 24.50400 ;
    END
  END wd_in[253]
  PIN wd_in[254]
    DIRECTION INPUT ;
    USE SIGNAL ;
    PORT
      LAYER M4 ;
      RECT 0.00000 24.52800 0.03600 24.55200 ;
    END
  END wd_in[254]
  PIN wd_in[255]
    DIRECTION INPUT ;
    USE SIGNAL ;
    PORT
      LAYER M4 ;
      RECT 0.00000 24.57600 0.03600 24.60000 ;
    END
  END wd_in[255]
  PIN addr_in[0]
    DIRECTION INPUT ;
    USE SIGNAL ;
    PORT
      LAYER M4 ;
      RECT 0.00000 24.62400 0.03600 24.64800 ;
    END
  END addr_in[0]
  PIN addr_in[1]
    DIRECTION INPUT ;
    USE SIGNAL ;
    PORT
      LAYER M4 ;
      RECT 0.00000 24.67200 0.03600 24.69600 ;
    END
  END addr_in[1]
  PIN addr_in[2]
    DIRECTION INPUT ;
    USE SIGNAL ;
    PORT
      LAYER M4 ;
      RECT 0.00000 24.72000 0.03600 24.74400 ;
    END
  END addr_in[2]
  PIN addr_in[3]
    DIRECTION INPUT ;
    USE SIGNAL ;
    PORT
      LAYER M4 ;
      RECT 0.00000 24.76800 0.03600 24.79200 ;
    END
  END addr_in[3]
  PIN addr_in[4]
    DIRECTION INPUT ;
    USE SIGNAL ;
    PORT
      LAYER M4 ;
      RECT 0.00000 24.81600 0.03600 24.84000 ;
    END
  END addr_in[4]
  PIN addr_in[5]
    DIRECTION INPUT ;
    USE SIGNAL ;
    PORT
      LAYER M4 ;
      RECT 0.00000 24.86400 0.03600 24.88800 ;
    END
  END addr_in[5]
  PIN we_in
    DIRECTION INPUT ;
    USE SIGNAL ;
    PORT
      LAYER M4 ;
      RECT 0.00000 24.91200 0.03600 24.93600 ;
    END
  END we_in
  PIN clk
    DIRECTION INPUT ;
    USE SIGNAL ;
    PORT
      LAYER M4 ;
      RECT 0.00000 24.96000 0.03600 24.98400 ;
    END
  END clk
  PIN ce_in
    DIRECTION INPUT ;
    USE SIGNAL ;
    PORT
      LAYER M4 ;
      RECT 0.00000 25.00800 0.03600 25.03200 ;
    END
  END ce_in
  PIN VDD
    DIRECTION INOUT ;
    USE POWER ;
    PORT
      LAYER M4 ;
      RECT 0.09600 0.38400 33.15400 0.48000 ;
      RECT 0.09600 1.15200 33.15400 1.24800 ;
      RECT 0.09600 1.92000 33.15400 2.01600 ;
      RECT 0.09600 2.68800 33.15400 2.78400 ;
      RECT 0.09600 3.45600 33.15400 3.55200 ;
      RECT 0.09600 4.22400 33.15400 4.32000 ;
      RECT 0.09600 4.99200 33.15400 5.08800 ;
      RECT 0.09600 5.76000 33.15400 5.85600 ;
      RECT 0.09600 6.52800 33.15400 6.62400 ;
      RECT 0.09600 7.29600 33.15400 7.39200 ;
      RECT 0.09600 8.06400 33.15400 8.16000 ;
      RECT 0.09600 8.83200 33.15400 8.92800 ;
      RECT 0.09600 9.60000 33.15400 9.69600 ;
      RECT 0.09600 10.36800 33.15400 10.46400 ;
      RECT 0.09600 11.13600 33.15400 11.23200 ;
      RECT 0.09600 11.90400 33.15400 12.00000 ;
      RECT 0.09600 12.67200 33.15400 12.76800 ;
      RECT 0.09600 13.44000 33.15400 13.53600 ;
      RECT 0.09600 14.20800 33.15400 14.30400 ;
      RECT 0.09600 14.97600 33.15400 15.07200 ;
      RECT 0.09600 15.74400 33.15400 15.84000 ;
      RECT 0.09600 16.51200 33.15400 16.60800 ;
      RECT 0.09600 17.28000 33.15400 17.37600 ;
      RECT 0.09600 18.04800 33.15400 18.14400 ;
      RECT 0.09600 18.81600 33.15400 18.91200 ;
      RECT 0.09600 19.58400 33.15400 19.68000 ;
      RECT 0.09600 20.35200 33.15400 20.44800 ;
      RECT 0.09600 21.12000 33.15400 21.21600 ;
      RECT 0.09600 21.88800 33.15400 21.98400 ;
      RECT 0.09600 22.65600 33.15400 22.75200 ;
      RECT 0.09600 23.42400 33.15400 23.52000 ;
      RECT 0.09600 24.19200 33.15400 24.28800 ;
      RECT 0.09600 24.96000 33.15400 25.05600 ;
    END
  END VDD
  PIN VSS
    DIRECTION INOUT ;
    USE GROUND ;
    PORT
      LAYER M4 ;
      RECT 0.09600 0.00000 33.15400 0.09600 ;
      RECT 0.09600 0.76800 33.15400 0.86400 ;
      RECT 0.09600 1.53600 33.15400 1.63200 ;
      RECT 0.09600 2.30400 33.15400 2.40000 ;
      RECT 0.09600 3.07200 33.15400 3.16800 ;
      RECT 0.09600 3.84000 33.15400 3.93600 ;
      RECT 0.09600 4.60800 33.15400 4.70400 ;
      RECT 0.09600 5.37600 33.15400 5.47200 ;
      RECT 0.09600 6.14400 33.15400 6.24000 ;
      RECT 0.09600 6.91200 33.15400 7.00800 ;
      RECT 0.09600 7.68000 33.15400 7.77600 ;
      RECT 0.09600 8.44800 33.15400 8.54400 ;
      RECT 0.09600 9.21600 33.15400 9.31200 ;
      RECT 0.09600 9.98400 33.15400 10.08000 ;
      RECT 0.09600 10.75200 33.15400 10.84800 ;
      RECT 0.09600 11.52000 33.15400 11.61600 ;
      RECT 0.09600 12.28800 33.15400 12.38400 ;
      RECT 0.09600 13.05600 33.15400 13.15200 ;
      RECT 0.09600 13.82400 33.15400 13.92000 ;
      RECT 0.09600 14.59200 33.15400 14.68800 ;
      RECT 0.09600 15.36000 33.15400 15.45600 ;
      RECT 0.09600 16.12800 33.15400 16.22400 ;
      RECT 0.09600 16.89600 33.15400 16.99200 ;
      RECT 0.09600 17.66400 33.15400 17.76000 ;
      RECT 0.09600 18.43200 33.15400 18.52800 ;
      RECT 0.09600 19.20000 33.15400 19.29600 ;
      RECT 0.09600 19.96800 33.15400 20.06400 ;
      RECT 0.09600 20.73600 33.15400 20.83200 ;
      RECT 0.09600 21.50400 33.15400 21.60000 ;
      RECT 0.09600 22.27200 33.15400 22.36800 ;
      RECT 0.09600 23.04000 33.15400 23.13600 ;
      RECT 0.09600 23.80800 33.15400 23.90400 ;
      RECT 0.09600 24.57600 33.15400 24.67200 ;
    END
  END VSS
  OBS
    LAYER M1 ;
    RECT 0 0 33.25000 25.20000 ;
    LAYER M2 ;
    RECT 0 0 33.25000 25.20000 ;
    LAYER M3 ;
    RECT 0 0 33.25000 25.20000 ;
    LAYER M4 ;
    RECT 0 0 33.25000 25.20000 ;
  END
END cva6_sram_64x256

END LIBRARY
